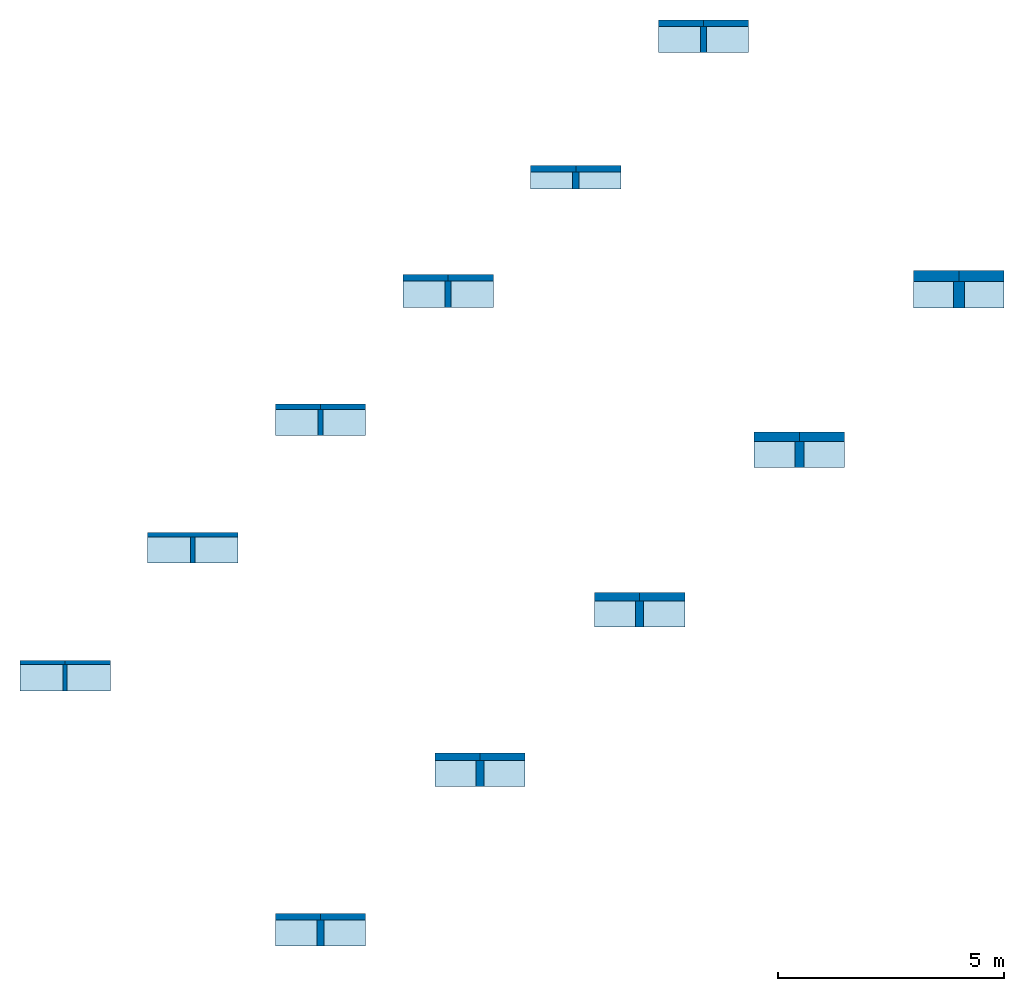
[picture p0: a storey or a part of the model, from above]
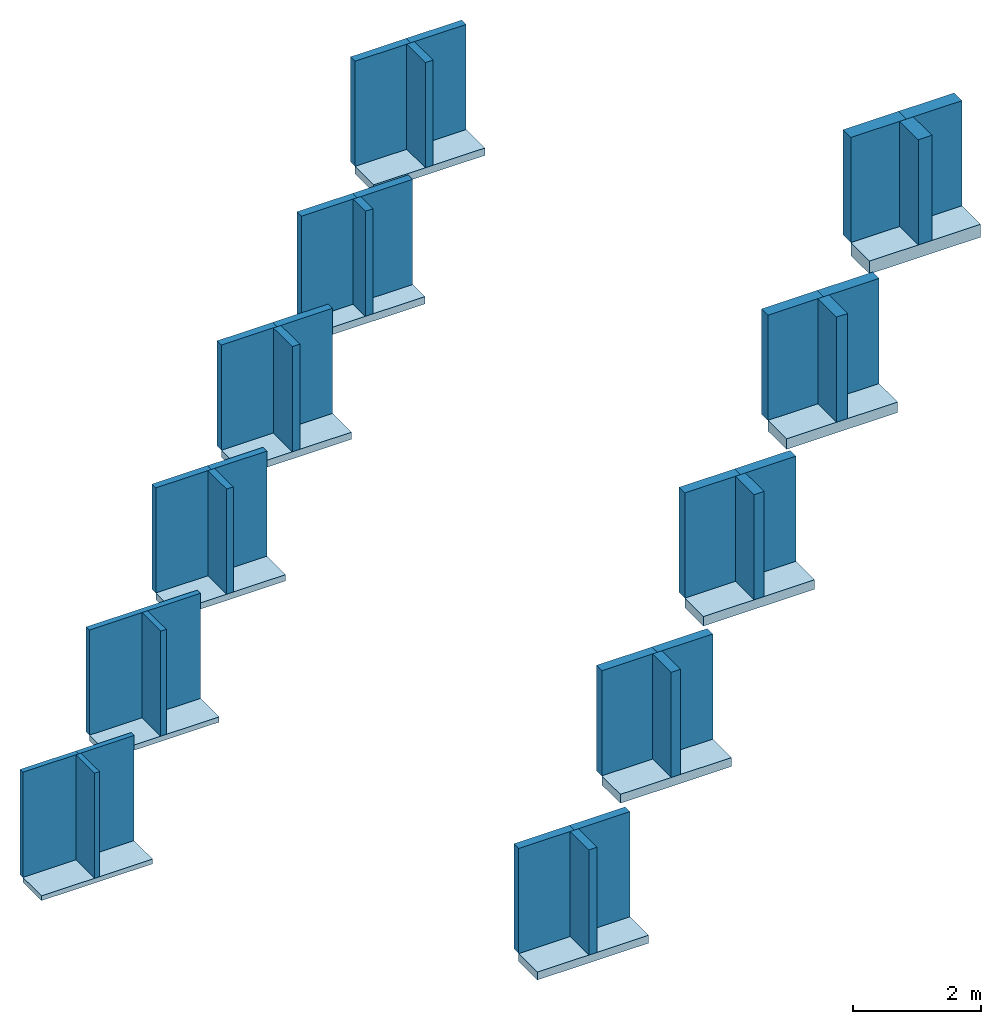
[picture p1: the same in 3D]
Properties of the parts of a building model (IFC2X3), part 1 of 2

# File
Description: ViewDefinition [CoordinationView_V2.0, QuantityTakeOffAddOnView]
Time: 2021-05-19T20:09:39
Written by: The EXPRESS Data Manager Version 5.02.0100.07 : 28 Aug 2013
Made in: 20190108_1515(x64) - Exporter 19.1.0.0 - Alternate UI 19.1.0.0
Comment: STEP Physical File produced by: The EXPRESS Data Manager Version 5.02.0100.07 : 28 Aug 2013 * Module: EDMstepFileFactory/EDMstandAlone * Creation date: Wed May 19 20:09:39 2021 * Host: lt-026 * Database: C:\Users\WF2BF~1.POE\AppData\Local\Temp\{AAD45BE6-D77A-4F7A-87E2-F376C7E0D897}\ifc * Database version: 5507 * Database creation date: Wed May 19 20:09:38 2021 * Schema: IFC2X3 * Model: DataRepository.ifc * Model creation date: Wed May 19 20:09:38 2021 * Header model: DataRepository.ifc_HeaderModel * Header model creation date: Wed May 19 20:09:38 2021 * EDMuser: sdai-user * EDMgroup: sdai-group * License ID and type: 5605 : Permanent license. Expiry date: * EDMstepFileFactory options: 020000

# IfcSite, Default
RefLatitude: 42, 24, 53, 508911; RefLongitude: -71, -15, -29, -58837; RefElevation: 0 mm
Other - Category: Project Information

# IfcBuilding
Pset_BuildingCommon - NumberOfStoreys: 2
Pset_ProductRequirements - Category: Project Information; sets with these values: 2

# IfcBuildingStorey: Level:NL_00_niveau (2)
Pset_ProductRequirements - Category: Levels
Dimensions - Computation Height: 0 mm
Identity Data - Structural: no; Building Story: yes
Other - Category: Levels; Family: Level: NL_00_niveau; Family and Type: Level: NL_00_niveau; Type: Level: NL_00_niveau; Type Id: Level: NL_00_niveau
Constraints(Type) - Elevation Base: Project Base Point
Graphics(Type) - Color: 16711680; Line Pattern: NL_00_niveau; Line Weight: 1; Symbol: NLRS_00_LAB_niveau bovenkant_gen_cadix: 1.8mm; Symbol at End 1 Default: no; Symbol at End 2 Default: yes
Identity Data(Type) - Type Name: NL_00_niveau
Other(Type) - Category: Levels; Family Name: Level
Name | LongName = Pset_AirSideSystemInformation, Name = Pset_ProductRequirements, Name = Identity Data, Name | Elevation (mm) = Constraints, Elevation (mm)
Begane grond | Begane grond | 0
Lengte | Lengte | 2000

# IfcRoof: Basic Roof:NLRS_27_RO_Naturoll 032_100x580x2700mm, Basic Roof:NLRS_27_RO_Naturoll 032_100x580x2700mm:25398
In: Lengte
Classification: 27 Daken (Uniformat)
Pset_ElementShading - Roughness: 304.8 mm
Pset_ManufacturerTypeInformation - Manufacturer: Knauf Insulation B.V.
Pset_ProductRequirements - Category: Roofs
Pset_QuantityTakeOff - Reference: NLRS_27_RO_Naturoll 032_100x580x2700mm
Pset_RoofCommon - IsExternal: yes; Reference: NLRS_27_RO_Naturoll 032_100x580x2700mm; ProjectedArea: 1.16 m2; TotalArea: 1.16 m2
Constraints - Related to Mass: no; Room Bounding: yes; Base Level: Level: Lengte; Base Offset From Level: 0 mm; Cutoff Offset: 0 mm
Construction - Fascia Depth: 0 mm; Rafter Cut: Plumb Cut; Maximum Ridge Height: 2100 mm
Dimensions - Area: 1.16 m2; Thickness: 100 mm; Volume: 0.116 m3
Other - Category: Roofs; Family: Basic Roof: NLRS_27_RO_Naturoll 032_100x580x2700mm; Family and Type: Basic Roof: NLRS_27_RO_Naturoll 032_100x580x2700mm; Type: Basic Roof: NLRS_27_RO_Naturoll 032_100x580x2700mm; Type Id: Basic Roof: NLRS_27_RO_Naturoll 032_100x580x2700mm
Phasing - Phase Created: New Construction
Analytical Properties(Type) - Roughness: 1; Thermal mass: 0; Absorptance: 0.1; Heat Transfer Coefficient (U): 0.32; Thermal Resistance (R): 3.125
Construction(Type) - Default Thickness: 100 mm
Data(Type) - rollen / pak: 2; pak (m2): 3.13; pakken / pallet: 32; pallet (m2): 100.22
Energy Analysis(Type) - kortstondige waterabsorptie: WS; langdurige waterabsorptie: WL(P); luchtstroomweerstand: Afr5; warmtegeleidingscoëfficiënt: 0.032; warmteweerstand: 3.1; waterdamptransmissie / waterdampdiffusie weerstandsfactor: MU1
General(Type) - NLRS_C_content_creator: Cadix; NLRS_C_content_versie: V1.0
Graphics(Type) - Coarse Scale Fill Color: 0
Identity Data(Type) - Type Image: Raster image: Naturoll 032 .jpg (2); Assembly Code: 27; Assembly Description: Daken; Description: Naturoll 032 - 100mm; DoP nummer (Declaration of performance): G4220OPCPR; email: customerservice.nl@knaufinsulation.com; Manufacturer: Knauf Insulation B.V.; Model: Naturoll 032 is een onbeklede glaswoldeken met ECOSE® Technology; NLRS_C_Code_Brandklasse: A1; phone: +31(0)162-421245; product URL: https://www.knaufinsulation.nl/producten-van-knauf-insulation/naturoll-032; Type Name: NLRS_27_RO_Naturoll 032_100x580x2700mm; URL: www.knaufinsulation.nl
Model Properties(Type) - diktebereik: 30 - 270; diktetolerantie: T4
Other(Type) - Category: Roofs; Family Name: Basic Roof

# IfcRoof: Basic Roof:NLRS_27_RO_Naturoll 032_120x580x2700mm, Basic Roof:NLRS_27_RO_Naturoll 032_120x580x2700mm:25438
In: Lengte
Classification: 27 Daken (Uniformat)
Pset_ElementShading - Roughness: 304.8 mm
Pset_ManufacturerTypeInformation - Manufacturer: Knauf Insulation B.V.
Pset_ProductRequirements - Category: Roofs
Pset_QuantityTakeOff - Reference: NLRS_27_RO_Naturoll 032_120x580x2700mm
Pset_RoofCommon - IsExternal: yes; Reference: NLRS_27_RO_Naturoll 032_120x580x2700mm; ProjectedArea: 1.16 m2; TotalArea: 1.16 m2
Constraints - Related to Mass: no; Room Bounding: yes; Base Level: Level: Lengte; Base Offset From Level: 0 mm; Cutoff Offset: 0 mm
Construction - Fascia Depth: 0 mm; Rafter Cut: Plumb Cut; Maximum Ridge Height: 2120 mm
Dimensions - Area: 1.16 m2; Thickness: 120 mm; Volume: 0.1392 m3
Other - Category: Roofs; Family: Basic Roof: NLRS_27_RO_Naturoll 032_120x580x2700mm; Family and Type: Basic Roof: NLRS_27_RO_Naturoll 032_120x580x2700mm; Type: Basic Roof: NLRS_27_RO_Naturoll 032_120x580x2700mm; Type Id: Basic Roof: NLRS_27_RO_Naturoll 032_120x580x2700mm
Phasing - Phase Created: New Construction
Analytical Properties(Type) - Roughness: 1; Thermal mass: 0; Absorptance: 0.1; Heat Transfer Coefficient (U): 0.266667; Thermal Resistance (R): 3.75
Construction(Type) - Default Thickness: 120 mm
Data(Type) - rollen / pak: 2; pak (m2): 3.13; pakken / pallet: 24; pallet (m2): 75.17
Energy Analysis(Type) - kortstondige waterabsorptie: WS; langdurige waterabsorptie: WL(P); luchtstroomweerstand: Afr5; warmtegeleidingscoëfficiënt: 0.032; warmteweerstand: 3.75; waterdamptransmissie / waterdampdiffusie weerstandsfactor: MU1
General(Type) - NLRS_C_content_creator: Cadix; NLRS_C_content_versie: V1.0
Graphics(Type) - Coarse Scale Fill Color: 0
Identity Data(Type) - Type Image: Raster image: Naturoll 032 .jpg (2); Assembly Code: 27; Assembly Description: Daken; Description: Naturoll 032 - 120mm; DoP nummer (Declaration of performance): G4220OPCPR; email: customerservice.nl@knaufinsulation.com; Manufacturer: Knauf Insulation B.V.; Model: Naturoll 032 is een onbeklede glaswoldeken met ECOSE® Technology; NLRS_C_Code_Brandklasse: A1; phone: +31(0)162-421245; product URL: https://www.knaufinsulation.nl/producten-van-knauf-insulation/naturoll-032; Type Name: NLRS_27_RO_Naturoll 032_120x580x2700mm; URL: www.knaufinsulation.nl
Model Properties(Type) - diktebereik: 30 - 270; diktetolerantie: T4
Other(Type) - Category: Roofs; Family Name: Basic Roof

# IfcRoof: Basic Roof:NLRS_27_RO_Naturoll 032_135x590x2700mm, Basic Roof:NLRS_27_RO_Naturoll 032_135x590x2700mm:25464
In: Lengte
Classification: 27 Daken (Uniformat)
Pset_ElementShading - Roughness: 304.8 mm
Pset_ManufacturerTypeInformation - Manufacturer: Knauf Insulation B.V.
Pset_ProductRequirements - Category: Roofs
Pset_QuantityTakeOff - Reference: NLRS_27_RO_Naturoll 032_135x590x2700mm
Pset_RoofCommon - IsExternal: yes; Reference: NLRS_27_RO_Naturoll 032_135x590x2700mm; ProjectedArea: 1.18 m2; TotalArea: 1.18 m2
Constraints - Related to Mass: no; Room Bounding: yes; Base Level: Level: Lengte; Base Offset From Level: 0 mm; Cutoff Offset: 0 mm
Construction - Fascia Depth: 0 mm; Rafter Cut: Plumb Cut; Maximum Ridge Height: 2135 mm
Dimensions - Area: 1.18 m2; Thickness: 135 mm; Volume: 0.1593 m3
Other - Category: Roofs; Family: Basic Roof: NLRS_27_RO_Naturoll 032_135x590x2700mm; Family and Type: Basic Roof: NLRS_27_RO_Naturoll 032_135x590x2700mm; Type: Basic Roof: NLRS_27_RO_Naturoll 032_135x590x2700mm; Type Id: Basic Roof: NLRS_27_RO_Naturoll 032_135x590x2700mm
Phasing - Phase Created: New Construction
Analytical Properties(Type) - Roughness: 1; Thermal mass: 0; Absorptance: 0.1; Heat Transfer Coefficient (U): 0.237037; Thermal Resistance (R): 4.21875
Construction(Type) - Default Thickness: 135 mm
Data(Type) - rollen / pak: 2; pak (m2): 3.19; pakken / pallet: 24; pallet (m2): 76.46
Energy Analysis(Type) - kortstondige waterabsorptie: WS; langdurige waterabsorptie: WL(P); luchtstroomweerstand: Afr5; warmtegeleidingscoëfficiënt: 0.032; warmteweerstand: 4.2; waterdamptransmissie / waterdampdiffusie weerstandsfactor: MU1
General(Type) - NLRS_C_content_creator: Cadix; NLRS_C_content_versie: V1.0
Graphics(Type) - Coarse Scale Fill Color: 0
Identity Data(Type) - Type Image: Raster image: Naturoll 032 .jpg (2); Assembly Code: 27; Assembly Description: Daken; Description: Naturoll 032 - 135mm; DoP nummer (Declaration of performance): G4220OPCPR; email: customerservice.nl@knaufinsulation.com; Manufacturer: Knauf Insulation B.V.; Model: Naturoll 032 is een onbeklede glaswoldeken met ECOSE® Technology; NLRS_C_Code_Brandklasse: A1; phone: +31(0)162-421245; product URL: https://www.knaufinsulation.nl/producten-van-knauf-insulation/naturoll-032; Type Name: NLRS_27_RO_Naturoll 032_135x590x2700mm; URL: www.knaufinsulation.nl
Model Properties(Type) - diktebereik: 30 - 270; diktetolerantie: T4
Other(Type) - Category: Roofs; Family Name: Basic Roof

# IfcRoof: Basic Roof:NLRS_27_RO_Naturoll 032_140x380x2700mm, Basic Roof:NLRS_27_RO_Naturoll 032_140x380x2700mm:25490
In: Lengte
Classification: 27 Daken (Uniformat)
Pset_ElementShading - Roughness: 304.8 mm
Pset_ManufacturerTypeInformation - Manufacturer: Knauf Insulation B.V.
Pset_ProductRequirements - Category: Roofs
Pset_QuantityTakeOff - Reference: NLRS_27_RO_Naturoll 032_140x380x2700mm
Pset_RoofCommon - IsExternal: yes; Reference: NLRS_27_RO_Naturoll 032_140x380x2700mm; ProjectedArea: 0.76 m2; TotalArea: 0.76 m2
Constraints - Related to Mass: no; Room Bounding: yes; Base Level: Level: Lengte; Base Offset From Level: 0 mm; Cutoff Offset: 0 mm
Construction - Fascia Depth: 0 mm; Rafter Cut: Plumb Cut; Maximum Ridge Height: 2140 mm
Dimensions - Area: 0.76 m2; Thickness: 140 mm; Volume: 0.1064 m3
Other - Category: Roofs; Family: Basic Roof: NLRS_27_RO_Naturoll 032_140x380x2700mm; Family and Type: Basic Roof: NLRS_27_RO_Naturoll 032_140x380x2700mm; Type: Basic Roof: NLRS_27_RO_Naturoll 032_140x380x2700mm; Type Id: Basic Roof: NLRS_27_RO_Naturoll 032_140x380x2700mm
Phasing - Phase Created: New Construction
Analytical Properties(Type) - Roughness: 1; Thermal mass: 0; Absorptance: 0.1; Heat Transfer Coefficient (U): 0.228571; Thermal Resistance (R): 4.375
Construction(Type) - Default Thickness: 140 mm
Data(Type) - rollen / pak: 3; pak (m2): 3.08; pakken / pallet: 24; pallet (m2): 73.87
Energy Analysis(Type) - kortstondige waterabsorptie: WS; langdurige waterabsorptie: WL(P); luchtstroomweerstand: Afr5; warmtegeleidingscoëfficiënt: 0.032; warmteweerstand: 4.35; waterdamptransmissie / waterdampdiffusie weerstandsfactor: MU1
General(Type) - NLRS_C_content_creator: Cadix; NLRS_C_content_versie: V1.0
Graphics(Type) - Coarse Scale Fill Color: 0
Identity Data(Type) - Type Image: Raster image: Naturoll 032 .jpg (2); Assembly Code: 27; Assembly Description: Daken; Description: Naturoll 032 - 140mm; DoP nummer (Declaration of performance): G4220OPCPR; email: customerservice.nl@knaufinsulation.com; Manufacturer: Knauf Insulation B.V.; Model: Naturoll 032 is een onbeklede glaswoldeken met ECOSE® Technology; NLRS_C_Code_Brandklasse: A1; phone: +31(0)162-421245; product URL: https://www.knaufinsulation.nl/producten-van-knauf-insulation/naturoll-032; Type Name: NLRS_27_RO_Naturoll 032_140x380x2700mm; URL: www.knaufinsulation.nl
Model Properties(Type) - diktebereik: 30 - 270; diktetolerantie: T4
Other(Type) - Category: Roofs; Family Name: Basic Roof

# IfcRoof: Basic Roof:NLRS_27_RO_Naturoll 032_140x580x2700mm, Basic Roof:NLRS_27_RO_Naturoll 032_140x580x2700mm:25516
In: Lengte
Classification: 27 Daken (Uniformat)
Pset_ElementShading - Roughness: 304.8 mm
Pset_ManufacturerTypeInformation - Manufacturer: Knauf Insulation B.V.
Pset_ProductRequirements - Category: Roofs
Pset_QuantityTakeOff - Reference: NLRS_27_RO_Naturoll 032_140x580x2700mm
Pset_RoofCommon - IsExternal: yes; Reference: NLRS_27_RO_Naturoll 032_140x580x2700mm; ProjectedArea: 1.16 m2; TotalArea: 1.16 m2
Constraints - Related to Mass: no; Room Bounding: yes; Base Level: Level: Lengte; Base Offset From Level: 0 mm; Cutoff Offset: 0 mm
Construction - Fascia Depth: 0 mm; Rafter Cut: Plumb Cut; Maximum Ridge Height: 2140 mm
Dimensions - Area: 1.16 m2; Thickness: 140 mm; Volume: 0.1624 m3
Other - Category: Roofs; Family: Basic Roof: NLRS_27_RO_Naturoll 032_140x580x2700mm; Family and Type: Basic Roof: NLRS_27_RO_Naturoll 032_140x580x2700mm; Type: Basic Roof: NLRS_27_RO_Naturoll 032_140x580x2700mm; Type Id: Basic Roof: NLRS_27_RO_Naturoll 032_140x580x2700mm
Phasing - Phase Created: New Construction
Analytical Properties(Type) - Roughness: 1; Thermal mass: 0; Absorptance: 0.1; Heat Transfer Coefficient (U): 0.228571; Thermal Resistance (R): 4.375
Construction(Type) - Default Thickness: 140 mm
Data(Type) - rollen / pak: 2; pak (m2): 3.13; pakken / pallet: 24; pallet (m2): 75.17
Energy Analysis(Type) - kortstondige waterabsorptie: WS; langdurige waterabsorptie: WL(P); luchtstroomweerstand: Afr5; warmtegeleidingscoëfficiënt: 0.032; warmteweerstand: 4.35; waterdamptransmissie / waterdampdiffusie weerstandsfactor: MU1
General(Type) - NLRS_C_content_creator: Cadix; NLRS_C_content_versie: V1.0
Graphics(Type) - Coarse Scale Fill Color: 0
Identity Data(Type) - Type Image: Raster image: Naturoll 032 .jpg (2); Assembly Code: 27; Assembly Description: Daken; Description: Naturoll 032 - 140mm; DoP nummer (Declaration of performance): G4220OPCPR; email: customerservice.nl@knaufinsulation.com; Manufacturer: Knauf Insulation B.V.; Model: Naturoll 032 is een onbeklede glaswoldeken met ECOSE® Technology; NLRS_C_Code_Brandklasse: A1; phone: +31(0)162-421245; product URL: https://www.knaufinsulation.nl/producten-van-knauf-insulation/naturoll-032; Type Name: NLRS_27_RO_Naturoll 032_140x580x2700mm; URL: www.knaufinsulation.nl
Model Properties(Type) - diktebereik: 30 - 270; diktetolerantie: T4
Other(Type) - Category: Roofs; Family Name: Basic Roof

# IfcRoof: Basic Roof:NLRS_27_RO_Naturoll 032_150x580x2700mm, Basic Roof:NLRS_27_RO_Naturoll 032_150x580x2700mm:26574
In: Lengte
Classification: 27 Daken (Uniformat)
Pset_ElementShading - Roughness: 304.8 mm
Pset_ManufacturerTypeInformation - Manufacturer: Knauf Insulation B.V.
Pset_ProductRequirements - Category: Roofs
Pset_QuantityTakeOff - Reference: NLRS_27_RO_Naturoll 032_150x580x2700mm
Pset_RoofCommon - IsExternal: yes; Reference: NLRS_27_RO_Naturoll 032_150x580x2700mm; ProjectedArea: 1.16 m2; TotalArea: 1.16 m2
Constraints - Related to Mass: no; Room Bounding: yes; Base Level: Level: Lengte; Base Offset From Level: 0 mm; Cutoff Offset: 0 mm
Construction - Fascia Depth: 0 mm; Rafter Cut: Plumb Cut; Maximum Ridge Height: 2150 mm
Dimensions - Area: 1.16 m2; Thickness: 150 mm; Volume: 0.174 m3
Other - Category: Roofs; Family: Basic Roof: NLRS_27_RO_Naturoll 032_150x580x2700mm; Family and Type: Basic Roof: NLRS_27_RO_Naturoll 032_150x580x2700mm; Type: Basic Roof: NLRS_27_RO_Naturoll 032_150x580x2700mm; Type Id: Basic Roof: NLRS_27_RO_Naturoll 032_150x580x2700mm
Phasing - Phase Created: New Construction
Analytical Properties(Type) - Roughness: 1; Thermal mass: 0; Absorptance: 0.1; Heat Transfer Coefficient (U): 0.213333; Thermal Resistance (R): 4.6875
Construction(Type) - Default Thickness: 150 mm
Data(Type) - rollen / pak: 2; pak (m2): 3.13; pakken / pallet: 24; pallet (m2): 75.17
Energy Analysis(Type) - kortstondige waterabsorptie: WS; langdurige waterabsorptie: WL(P); luchtstroomweerstand: Afr5; warmtegeleidingscoëfficiënt: 0.032; warmteweerstand: 4.65; waterdamptransmissie / waterdampdiffusie weerstandsfactor: MU1
General(Type) - NLRS_C_content_creator: Cadix; NLRS_C_content_versie: V1.0
Graphics(Type) - Coarse Scale Fill Color: 0
Identity Data(Type) - Type Image: Raster image: Naturoll 032 .jpg (2); Assembly Code: 27; Assembly Description: Daken; Description: Naturoll 032 - 150mm; DoP nummer (Declaration of performance): G4220OPCPR; email: customerservice.nl@knaufinsulation.com; Manufacturer: Knauf Insulation B.V.; Model: Naturoll 032 is een onbeklede glaswoldeken met ECOSE® Technology; NLRS_C_Code_Brandklasse: A1; phone: +31(0)162-421245; product URL: https://www.knaufinsulation.nl/producten-van-knauf-insulation/naturoll-032; Type Name: NLRS_27_RO_Naturoll 032_150x580x2700mm; URL: www.knaufinsulation.nl
Model Properties(Type) - diktebereik: 30 - 270; diktetolerantie: T4
Other(Type) - Category: Roofs; Family Name: Basic Roof

# IfcRoof: Basic Roof:NLRS_27_RO_Naturoll 032_170x580x3500mm, Basic Roof:NLRS_27_RO_Naturoll 032_170x580x3500mm:26836
In: Lengte
Classification: 27 Daken (Uniformat)
Pset_ElementShading - Roughness: 304.8 mm
Pset_ManufacturerTypeInformation - Manufacturer: Knauf Insulation B.V.
Pset_ProductRequirements - Category: Roofs
Pset_QuantityTakeOff - Reference: NLRS_27_RO_Naturoll 032_170x580x3500mm
Pset_RoofCommon - IsExternal: yes; Reference: NLRS_27_RO_Naturoll 032_170x580x3500mm; ProjectedArea: 1.16 m2; TotalArea: 1.16 m2
Constraints - Related to Mass: no; Room Bounding: yes; Base Level: Level: Lengte; Base Offset From Level: 0 mm; Cutoff Offset: 0 mm
Construction - Fascia Depth: 0 mm; Rafter Cut: Plumb Cut; Maximum Ridge Height: 2170 mm
Dimensions - Area: 1.16 m2; Thickness: 170 mm; Volume: 0.1972 m3
Other - Category: Roofs; Family: Basic Roof: NLRS_27_RO_Naturoll 032_170x580x3500mm; Family and Type: Basic Roof: NLRS_27_RO_Naturoll 032_170x580x3500mm; Type: Basic Roof: NLRS_27_RO_Naturoll 032_170x580x3500mm; Type Id: Basic Roof: NLRS_27_RO_Naturoll 032_170x580x3500mm
Phasing - Phase Created: New Construction
Analytical Properties(Type) - Roughness: 1; Thermal mass: 0; Absorptance: 0.1; Heat Transfer Coefficient (U): 0.188235; Thermal Resistance (R): 5.3125
Construction(Type) - Default Thickness: 170 mm
Data(Type) - rollen / pak: 2; pak (m2): 2.73; pakken / pallet: 24; pallet (m2): 65.42
Energy Analysis(Type) - kortstondige waterabsorptie: WS; langdurige waterabsorptie: WL(P); luchtstroomweerstand: Afr5; warmtegeleidingscoëfficiënt: 0.032; warmteweerstand: 5.3; waterdamptransmissie / waterdampdiffusie weerstandsfactor: MU1
General(Type) - NLRS_C_content_creator: Cadix; NLRS_C_content_versie: V1.0
Graphics(Type) - Coarse Scale Fill Color: 0
Identity Data(Type) - Type Image: Raster image: Naturoll 032 .jpg (2); Assembly Code: 27; Assembly Description: Daken; Description: Naturoll 032 - 170mm; DoP nummer (Declaration of performance): G4220OPCPR; email: customerservice.nl@knaufinsulation.com; Manufacturer: Knauf Insulation B.V.; Model: Naturoll 032 is een onbeklede glaswoldeken met ECOSE® Technology; NLRS_C_Code_Brandklasse: A1; phone: +31(0)162-421245; product URL: https://www.knaufinsulation.nl/producten-van-knauf-insulation/naturoll-032; Type Name: NLRS_27_RO_Naturoll 032_170x580x3500mm; URL: www.knaufinsulation.nl
Model Properties(Type) - diktebereik: 30 - 270; diktetolerantie: T4
Other(Type) - Category: Roofs; Family Name: Basic Roof

# IfcRoof: Basic Roof:NLRS_27_RO_Naturoll 032_180x580x2200mm, Basic Roof:NLRS_27_RO_Naturoll 032_180x580x2200mm:26894
In: Lengte
Classification: 27 Daken (Uniformat)
Pset_ElementShading - Roughness: 304.8 mm
Pset_ManufacturerTypeInformation - Manufacturer: Knauf Insulation B.V.
Pset_ProductRequirements - Category: Roofs
Pset_QuantityTakeOff - Reference: NLRS_27_RO_Naturoll 032_180x580x2200mm
Pset_RoofCommon - IsExternal: yes; Reference: NLRS_27_RO_Naturoll 032_180x580x2200mm; ProjectedArea: 1.16 m2; TotalArea: 1.16 m2
Constraints - Related to Mass: no; Room Bounding: yes; Base Level: Level: Lengte; Base Offset From Level: 0 mm; Cutoff Offset: 0 mm
Construction - Fascia Depth: 0 mm; Rafter Cut: Plumb Cut; Maximum Ridge Height: 2180 mm
Dimensions - Area: 1.16 m2; Thickness: 180 mm; Volume: 0.2088 m3
Other - Category: Roofs; Family: Basic Roof: NLRS_27_RO_Naturoll 032_180x580x2200mm; Family and Type: Basic Roof: NLRS_27_RO_Naturoll 032_180x580x2200mm; Type: Basic Roof: NLRS_27_RO_Naturoll 032_180x580x2200mm; Type Id: Basic Roof: NLRS_27_RO_Naturoll 032_180x580x2200mm
Phasing - Phase Created: New Construction
Analytical Properties(Type) - Roughness: 1; Thermal mass: 0; Absorptance: 0.1; Heat Transfer Coefficient (U): 0.177778; Thermal Resistance (R): 5.625
Construction(Type) - Default Thickness: 180 mm
Data(Type) - rollen / pak: 2; pak (m2): 2.55; pakken / pallet: 24; pallet (m2): 61.25
Energy Analysis(Type) - kortstondige waterabsorptie: WS; langdurige waterabsorptie: WL(P); luchtstroomweerstand: Afr5; warmtegeleidingscoëfficiënt: 0.032; warmteweerstand: 5.6; waterdamptransmissie / waterdampdiffusie weerstandsfactor: MU1
General(Type) - NLRS_C_content_creator: Cadix; NLRS_C_content_versie: V1.0
Graphics(Type) - Coarse Scale Fill Color: 0
Identity Data(Type) - Type Image: Raster image: Naturoll 032 .jpg (2); Assembly Code: 27; Assembly Description: Daken; Description: Naturoll 032 - 180mm; DoP nummer (Declaration of performance): G4220OPCPR; email: customerservice.nl@knaufinsulation.com; Manufacturer: Knauf Insulation B.V.; Model: Naturoll 032 is een onbeklede glaswoldeken met ECOSE® Technology; NLRS_C_Code_Brandklasse: A1; phone: +31(0)162-421245; product URL: https://www.knaufinsulation.nl/producten-van-knauf-insulation/naturoll-032; Type Name: NLRS_27_RO_Naturoll 032_180x580x2200mm; URL: www.knaufinsulation.nl
Model Properties(Type) - diktebereik: 30 - 270; diktetolerantie: T4
Other(Type) - Category: Roofs; Family Name: Basic Roof

# IfcRoof: Basic Roof:NLRS_27_RO_Naturoll 032_200x580x2000mm, Basic Roof:NLRS_27_RO_Naturoll 032_200x580x2000mm:26921
In: Lengte
Classification: 27 Daken (Uniformat)
Pset_ElementShading - Roughness: 304.8 mm
Pset_ManufacturerTypeInformation - Manufacturer: Knauf Insulation B.V.
Pset_ProductRequirements - Category: Roofs
Pset_QuantityTakeOff - Reference: NLRS_27_RO_Naturoll 032_200x580x2000mm
Pset_RoofCommon - IsExternal: yes; Reference: NLRS_27_RO_Naturoll 032_200x580x2000mm; ProjectedArea: 1.16 m2; TotalArea: 1.16 m2
Constraints - Related to Mass: no; Room Bounding: yes; Base Level: Level: Lengte; Base Offset From Level: 0 mm; Cutoff Offset: 0 mm
Construction - Fascia Depth: 0 mm; Rafter Cut: Plumb Cut; Maximum Ridge Height: 2200 mm
Dimensions - Area: 1.16 m2; Thickness: 200 mm; Volume: 0.232 m3
Other - Category: Roofs; Family: Basic Roof: NLRS_27_RO_Naturoll 032_200x580x2000mm; Family and Type: Basic Roof: NLRS_27_RO_Naturoll 032_200x580x2000mm; Type: Basic Roof: NLRS_27_RO_Naturoll 032_200x580x2000mm; Type Id: Basic Roof: NLRS_27_RO_Naturoll 032_200x580x2000mm
Phasing - Phase Created: New Construction
Analytical Properties(Type) - Roughness: 1; Thermal mass: 0; Absorptance: 0.1; Heat Transfer Coefficient (U): 0.16; Thermal Resistance (R): 6.25
Construction(Type) - Default Thickness: 200 mm
Data(Type) - rollen / pak: 2; pak (m2): 2.32; pakken / pallet: 24; pallet (m2): 55.68
Energy Analysis(Type) - kortstondige waterabsorptie: WS; langdurige waterabsorptie: WL(P); luchtstroomweerstand: Afr5; warmtegeleidingscoëfficiënt: 0.032; warmteweerstand: 6.25; waterdamptransmissie / waterdampdiffusie weerstandsfactor: MU1
General(Type) - NLRS_C_content_creator: Cadix; NLRS_C_content_versie: V1.0
Graphics(Type) - Coarse Scale Fill Color: 0
Identity Data(Type) - Type Image: Raster image: Naturoll 032 .jpg (2); Assembly Code: 27; Assembly Description: Daken; Description: Naturoll 032 - 200mm; DoP nummer (Declaration of performance): G4220OPCPR; email: customerservice.nl@knaufinsulation.com; Manufacturer: Knauf Insulation B.V.; Model: Naturoll 032 is een onbeklede glaswoldeken met ECOSE® Technology; NLRS_C_Code_Brandklasse: A1; phone: +31(0)162-421245; product URL: https://www.knaufinsulation.nl/producten-van-knauf-insulation/naturoll-032; Type Name: NLRS_27_RO_Naturoll 032_200x580x2000mm; URL: www.knaufinsulation.nl
Model Properties(Type) - diktebereik: 30 - 270; diktetolerantie: T4
Other(Type) - Category: Roofs; Family Name: Basic Roof

# IfcRoof: Basic Roof:NLRS_27_RO_Naturoll 032_245x580x2000mm, Basic Roof:NLRS_27_RO_Naturoll 032_245x580x2000mm:26948
In: Lengte
Classification: 27 Daken (Uniformat)
Pset_ElementShading - Roughness: 304.8 mm
Pset_ManufacturerTypeInformation - Manufacturer: Knauf Insulation B.V.
Pset_ProductRequirements - Category: Roofs
Pset_QuantityTakeOff - Reference: NLRS_27_RO_Naturoll 032_245x580x2000mm
Pset_RoofCommon - IsExternal: yes; Reference: NLRS_27_RO_Naturoll 032_245x580x2000mm; ProjectedArea: 1.16 m2; TotalArea: 1.16 m2
Constraints - Related to Mass: no; Room Bounding: yes; Base Level: Level: Lengte; Base Offset From Level: 0 mm; Cutoff Offset: 0 mm
Construction - Fascia Depth: 0 mm; Rafter Cut: Plumb Cut; Maximum Ridge Height: 2200 mm
Dimensions - Area: 1.16 m2; Thickness: 200 mm; Volume: 0.232 m3
Other - Category: Roofs; Family: Basic Roof: NLRS_27_RO_Naturoll 032_245x580x2000mm; Family and Type: Basic Roof: NLRS_27_RO_Naturoll 032_245x580x2000mm; Type: Basic Roof: NLRS_27_RO_Naturoll 032_245x580x2000mm; Type Id: Basic Roof: NLRS_27_RO_Naturoll 032_245x580x2000mm
Phasing - Phase Created: New Construction
Analytical Properties(Type) - Roughness: 1; Thermal mass: 0; Absorptance: 0.1; Heat Transfer Coefficient (U): 0.16; Thermal Resistance (R): 6.25
Construction(Type) - Default Thickness: 200 mm
Data(Type) - rollen / pak: 2; pak (m2): 2.32; pakken / pallet: 18; pallet (m2): 41.76
Energy Analysis(Type) - kortstondige waterabsorptie: WS; langdurige waterabsorptie: WL(P); luchtstroomweerstand: Afr5; warmtegeleidingscoëfficiënt: 0.032; warmteweerstand: 7.65; waterdamptransmissie / waterdampdiffusie weerstandsfactor: MU1
General(Type) - NLRS_C_content_creator: Cadix; NLRS_C_content_versie: V1.0
Graphics(Type) - Coarse Scale Fill Color: 0
Identity Data(Type) - Type Image: Raster image: Naturoll 032 .jpg (2); Assembly Code: 27; Assembly Description: Daken; Description: Naturoll 032 - 245mm; DoP nummer (Declaration of performance): G4220OPCPR; email: customerservice.nl@knaufinsulation.com; Manufacturer: Knauf Insulation B.V.; Model: Naturoll 032 is een onbeklede glaswoldeken met ECOSE® Technology; NLRS_C_Code_Brandklasse: A1; phone: +31(0)162-421245; product URL: https://www.knaufinsulation.nl/producten-van-knauf-insulation/naturoll-032; Type Name: NLRS_27_RO_Naturoll 032_245x580x2000mm; URL: www.knaufinsulation.nl
Model Properties(Type) - diktebereik: 30 - 270; diktetolerantie: T4
Other(Type) - Category: Roofs; Family Name: Basic Roof

# IfcRoof: Basic Roof:NLRS_27_RO_Naturoll 032_90x580x3500mm, Basic Roof:NLRS_27_RO_Naturoll 032_90x580x3500mm:25335
In: Lengte
Classification: 27 Daken (Uniformat)
Pset_ElementShading - Roughness: 304.8 mm
Pset_ManufacturerTypeInformation - Manufacturer: Knauf Insulation B.V.
Pset_ProductRequirements - Category: Roofs
Pset_QuantityTakeOff - Reference: NLRS_27_RO_Naturoll 032_90x580x3500mm
Pset_RoofCommon - IsExternal: yes; Reference: NLRS_27_RO_Naturoll 032_90x580x3500mm; ProjectedArea: 1.16 m2; TotalArea: 1.16 m2
Constraints - Related to Mass: no; Room Bounding: yes; Base Level: Level: Lengte; Base Offset From Level: 0 mm; Cutoff Offset: 0 mm
Construction - Fascia Depth: 0 mm; Maximum Ridge Height: 2090 mm; Rafter Cut: Plumb Cut
Dimensions - Area: 1.16 m2; Thickness: 90 mm; Volume: 0.1044 m3
Other - Category: Roofs; Family: Basic Roof: NLRS_27_RO_Naturoll 032_90x580x3500mm; Family and Type: Basic Roof: NLRS_27_RO_Naturoll 032_90x580x3500mm; Type: Basic Roof: NLRS_27_RO_Naturoll 032_90x580x3500mm; Type Id: Basic Roof: NLRS_27_RO_Naturoll 032_90x580x3500mm
Phasing - Phase Created: New Construction
Analytical Properties(Type) - Roughness: 1; Thermal mass: 0; Absorptance: 0.1; Heat Transfer Coefficient (U): 0.355556; Thermal Resistance (R): 2.8125
Construction(Type) - Default Thickness: 90 mm
Data(Type) - rollen / pak: 2; pak (m2): 4.06; pakken / pallet: 24; pallet (m2): 97.44
Energy Analysis(Type) - kortstondige waterabsorptie: WS; langdurige waterabsorptie: WL(P); luchtstroomweerstand: Afr5; warmtegeleidingscoëfficiënt: 0.032; warmteweerstand: 2.8; waterdamptransmissie / waterdampdiffusie weerstandsfactor: MU1
General(Type) - NLRS_C_content_creator: Cadix; NLRS_C_content_versie: V1.0
Graphics(Type) - Coarse Scale Fill Color: 0
Identity Data(Type) - Type Image: Raster image: Naturoll 032 .jpg (2); Assembly Code: 27; Assembly Description: Daken; Description: Naturoll 032 - 90mm; DoP nummer (Declaration of performance): G4220OPCPR; email: customerservice.nl@knaufinsulation.com; Manufacturer: Knauf Insulation B.V.; Model: Naturoll 032 is een onbeklede glaswoldeken met ECOSE® Technology; NLRS_C_Code_Brandklasse: A1; phone: +31(0)162-421245; product URL: https://www.knaufinsulation.nl/producten-van-knauf-insulation/naturoll-032; Type Name: NLRS_27_RO_Naturoll 032_90x580x3500mm; URL: www.knaufinsulation.nl
Model Properties(Type) - diktebereik: 30 - 270; diktetolerantie: T4
Other(Type) - Category: Roofs; Family Name: Basic Roof

# IfcSlab: Basic Roof:NLRS_27_RO_Naturoll 032_100x580x2700mm, Basic Roof:NLRS_27_RO_Naturoll 032_100x580x2700mm:25398
In: Lengte
PredefinedType: ROOF; Classification: 27 Daken (Uniformat); Material: Knauf Insulation_Ecose® glaswol_naturoll 032 100 mm
Pset_ElementShading - Roughness: 304.8 mm
Pset_ManufacturerTypeInformation - Manufacturer: Knauf Insulation B.V.
Pset_ProductRequirements - Category: Roofs
Pset_QuantityTakeOff - Reference: NLRS_27_RO_Naturoll 032_100x580x2700mm
Pset_ReinforcementBarPitchOfSlab - Description: Naturoll 032 - 100mm; Reference: NLRS_27_RO_Naturoll 032_100x580x2700mm
Pset_SlabCommon - PitchAngle: 0 deg; IsExternal: yes; Reference: NLRS_27_RO_Naturoll 032_100x580x2700mm; ThermalTransmittance: 0.32 kg/K/s3
BaseQuantities - GrossArea: 0.107768 m2; NetArea: 2.836 m2; GrossVolume: 10.7768 m3; NetVolume: 0.116 m3; Perimeter: 5160 mm; Width: 100 mm

# IfcSlab: Basic Roof:NLRS_27_RO_Naturoll 032_120x580x2700mm, Basic Roof:NLRS_27_RO_Naturoll 032_120x580x2700mm:25438
In: Lengte
PredefinedType: ROOF; Classification: 27 Daken (Uniformat); Material: Knauf Insulation_Ecose® glaswol_naturoll 032 120 mm
Pset_ElementShading - Roughness: 304.8 mm
Pset_ManufacturerTypeInformation - Manufacturer: Knauf Insulation B.V.
Pset_ProductRequirements - Category: Roofs
Pset_QuantityTakeOff - Reference: NLRS_27_RO_Naturoll 032_120x580x2700mm
Pset_ReinforcementBarPitchOfSlab - Description: Naturoll 032 - 120mm; Reference: NLRS_27_RO_Naturoll 032_120x580x2700mm
Pset_SlabCommon - PitchAngle: 0 deg; IsExternal: yes; Reference: NLRS_27_RO_Naturoll 032_120x580x2700mm; ThermalTransmittance: 0.266667 kg/K/s3
BaseQuantities - GrossArea: 0.107768 m2; NetArea: 2.9392 m2; GrossVolume: 12.9321 m3; NetVolume: 0.1392 m3; Perimeter: 5160 mm; Width: 120 mm

# IfcSlab: Basic Roof:NLRS_27_RO_Naturoll 032_135x590x2700mm, Basic Roof:NLRS_27_RO_Naturoll 032_135x590x2700mm:25464
In: Lengte
PredefinedType: ROOF; Classification: 27 Daken (Uniformat); Material: Knauf Insulation_Ecose® glaswol_naturoll 032 135 mm
Pset_ElementShading - Roughness: 304.8 mm
Pset_ManufacturerTypeInformation - Manufacturer: Knauf Insulation B.V.
Pset_ProductRequirements - Category: Roofs
Pset_QuantityTakeOff - Reference: NLRS_27_RO_Naturoll 032_135x590x2700mm
Pset_ReinforcementBarPitchOfSlab - Description: Naturoll 032 - 135mm; Reference: NLRS_27_RO_Naturoll 032_135x590x2700mm
Pset_SlabCommon - PitchAngle: 0 deg; IsExternal: yes; Reference: NLRS_27_RO_Naturoll 032_135x590x2700mm; ThermalTransmittance: 0.237037 kg/K/s3
BaseQuantities - GrossArea: 0.109626 m2; NetArea: 3.0593 m2; GrossVolume: 14.7995 m3; NetVolume: 0.1593 m3; Perimeter: 5180 mm; Width: 135 mm

# IfcSlab: Basic Roof:NLRS_27_RO_Naturoll 032_140x380x2700mm, Basic Roof:NLRS_27_RO_Naturoll 032_140x380x2700mm:25490
In: Lengte
PredefinedType: ROOF; Classification: 27 Daken (Uniformat); Material: Knauf Insulation_Ecose® glaswol_naturoll 032 140 mm
Pset_ElementShading - Roughness: 304.8 mm
Pset_ManufacturerTypeInformation - Manufacturer: Knauf Insulation B.V.
Pset_ProductRequirements - Category: Roofs
Pset_QuantityTakeOff - Reference: NLRS_27_RO_Naturoll 032_140x380x2700mm
Pset_ReinforcementBarPitchOfSlab - Description: Naturoll 032 - 140mm; Reference: NLRS_27_RO_Naturoll 032_140x380x2700mm
Pset_SlabCommon - PitchAngle: 0 deg; IsExternal: yes; Reference: NLRS_27_RO_Naturoll 032_140x380x2700mm; ThermalTransmittance: 0.228571 kg/K/s3
BaseQuantities - GrossArea: 0.0706063 m2; NetArea: 2.1864 m2; GrossVolume: 9.88488 m3; NetVolume: 0.1064 m3; Perimeter: 4760 mm; Width: 140 mm

# IfcSlab: Basic Roof:NLRS_27_RO_Naturoll 032_140x580x2700mm, Basic Roof:NLRS_27_RO_Naturoll 032_140x580x2700mm:25516
In: Lengte
PredefinedType: ROOF; Classification: 27 Daken (Uniformat); Material: Knauf Insulation_Ecose® glaswol_naturoll 032 140 mm
Pset_ElementShading - Roughness: 304.8 mm
Pset_ManufacturerTypeInformation - Manufacturer: Knauf Insulation B.V.
Pset_ProductRequirements - Category: Roofs
Pset_QuantityTakeOff - Reference: NLRS_27_RO_Naturoll 032_140x580x2700mm
Pset_ReinforcementBarPitchOfSlab - Description: Naturoll 032 - 140mm; Reference: NLRS_27_RO_Naturoll 032_140x580x2700mm
Pset_SlabCommon - PitchAngle: 0 deg; IsExternal: yes; Reference: NLRS_27_RO_Naturoll 032_140x580x2700mm; ThermalTransmittance: 0.228571 kg/K/s3
BaseQuantities - GrossArea: 0.107768 m2; NetArea: 3.0424 m2; GrossVolume: 15.0875 m3; NetVolume: 0.1624 m3; Perimeter: 5160 mm; Width: 140 mm

# IfcSlab: Basic Roof:NLRS_27_RO_Naturoll 032_150x580x2700mm, Basic Roof:NLRS_27_RO_Naturoll 032_150x580x2700mm:26574
In: Lengte
PredefinedType: ROOF; Classification: 27 Daken (Uniformat); Material: Knauf Insulation_Ecose® glaswol_naturoll 032 150 mm
Pset_ElementShading - Roughness: 304.8 mm
Pset_ManufacturerTypeInformation - Manufacturer: Knauf Insulation B.V.
Pset_ProductRequirements - Category: Roofs
Pset_QuantityTakeOff - Reference: NLRS_27_RO_Naturoll 032_150x580x2700mm
Pset_ReinforcementBarPitchOfSlab - Description: Naturoll 032 - 150mm; Reference: NLRS_27_RO_Naturoll 032_150x580x2700mm
Pset_SlabCommon - PitchAngle: 0 deg; IsExternal: yes; Reference: NLRS_27_RO_Naturoll 032_150x580x2700mm; ThermalTransmittance: 0.213333 kg/K/s3
BaseQuantities - GrossArea: 0.107768 m2; NetArea: 3.094 m2; GrossVolume: 16.1651 m3; NetVolume: 0.174 m3; Perimeter: 5160 mm; Width: 150 mm

# IfcSlab: Basic Roof:NLRS_27_RO_Naturoll 032_170x580x3500mm, Basic Roof:NLRS_27_RO_Naturoll 032_170x580x3500mm:26836
In: Lengte
PredefinedType: ROOF; Classification: 27 Daken (Uniformat); Material: Knauf Insulation_Ecose® glaswol_naturoll 032 170 mm
Pset_ElementShading - Roughness: 304.8 mm
Pset_ManufacturerTypeInformation - Manufacturer: Knauf Insulation B.V.
Pset_ProductRequirements - Category: Roofs
Pset_QuantityTakeOff - Reference: NLRS_27_RO_Naturoll 032_170x580x3500mm
Pset_ReinforcementBarPitchOfSlab - Description: Naturoll 032 - 170mm; Reference: NLRS_27_RO_Naturoll 032_170x580x3500mm
Pset_SlabCommon - PitchAngle: 0 deg; IsExternal: yes; Reference: NLRS_27_RO_Naturoll 032_170x580x3500mm; ThermalTransmittance: 0.188235 kg/K/s3
BaseQuantities - GrossArea: 0.107768 m2; NetArea: 3.1972 m2; GrossVolume: 18.3205 m3; NetVolume: 0.1972 m3; Perimeter: 5160 mm; Width: 170 mm

# IfcSlab: Basic Roof:NLRS_27_RO_Naturoll 032_180x580x2200mm, Basic Roof:NLRS_27_RO_Naturoll 032_180x580x2200mm:26894
In: Lengte
PredefinedType: ROOF; Classification: 27 Daken (Uniformat); Material: Knauf Insulation_Ecose® glaswol_naturoll 032 180 mm
Pset_ElementShading - Roughness: 304.8 mm
Pset_ManufacturerTypeInformation - Manufacturer: Knauf Insulation B.V.
Pset_ProductRequirements - Category: Roofs
Pset_QuantityTakeOff - Reference: NLRS_27_RO_Naturoll 032_180x580x2200mm
Pset_ReinforcementBarPitchOfSlab - Description: Naturoll 032 - 180mm; Reference: NLRS_27_RO_Naturoll 032_180x580x2200mm
Pset_SlabCommon - PitchAngle: 0 deg; IsExternal: yes; Reference: NLRS_27_RO_Naturoll 032_180x580x2200mm; ThermalTransmittance: 0.177778 kg/K/s3
BaseQuantities - GrossArea: 0.107768 m2; NetArea: 3.2488 m2; GrossVolume: 19.3982 m3; NetVolume: 0.2088 m3; Perimeter: 5160 mm; Width: 180 mm

# IfcSlab: Basic Roof:NLRS_27_RO_Naturoll 032_200x580x2000mm, Basic Roof:NLRS_27_RO_Naturoll 032_200x580x2000mm:26921
In: Lengte
PredefinedType: ROOF; Classification: 27 Daken (Uniformat); Material: Knauf Insulation_Ecose® glaswol_naturoll 032 200 mm
Pset_ElementShading - Roughness: 304.8 mm
Pset_ManufacturerTypeInformation - Manufacturer: Knauf Insulation B.V.
Pset_ProductRequirements - Category: Roofs
Pset_QuantityTakeOff - Reference: NLRS_27_RO_Naturoll 032_200x580x2000mm
Pset_ReinforcementBarPitchOfSlab - Description: Naturoll 032 - 200mm; Reference: NLRS_27_RO_Naturoll 032_200x580x2000mm
Pset_SlabCommon - PitchAngle: 0 deg; IsExternal: yes; Reference: NLRS_27_RO_Naturoll 032_200x580x2000mm; ThermalTransmittance: 0.16 kg/K/s3
BaseQuantities - GrossArea: 0.107768 m2; NetArea: 3.352 m2; GrossVolume: 21.5535 m3; NetVolume: 0.232 m3; Perimeter: 5160 mm; Width: 200 mm

# IfcSlab: Basic Roof:NLRS_27_RO_Naturoll 032_245x580x2000mm, Basic Roof:NLRS_27_RO_Naturoll 032_245x580x2000mm:26948
In: Lengte
PredefinedType: ROOF; Classification: 27 Daken (Uniformat); Material: Knauf Insulation_Ecose® glaswol_naturoll 032 200 mm
Pset_ElementShading - Roughness: 304.8 mm
Pset_ManufacturerTypeInformation - Manufacturer: Knauf Insulation B.V.
Pset_ProductRequirements - Category: Roofs
Pset_QuantityTakeOff - Reference: NLRS_27_RO_Naturoll 032_245x580x2000mm
Pset_ReinforcementBarPitchOfSlab - Description: Naturoll 032 - 245mm; Reference: NLRS_27_RO_Naturoll 032_245x580x2000mm
Pset_SlabCommon - PitchAngle: 0 deg; IsExternal: yes; Reference: NLRS_27_RO_Naturoll 032_245x580x2000mm; ThermalTransmittance: 0.16 kg/K/s3
BaseQuantities - GrossArea: 0.107768 m2; NetArea: 3.352 m2; GrossVolume: 21.5535 m3; NetVolume: 0.232 m3; Perimeter: 5160 mm; Width: 200 mm

# IfcSlab: Basic Roof:NLRS_27_RO_Naturoll 032_90x580x3500mm, Basic Roof:NLRS_27_RO_Naturoll 032_90x580x3500mm:25335
In: Lengte
PredefinedType: ROOF; Classification: 27 Daken (Uniformat); Material: Knauf Insulation_Ecose® glaswol_naturoll 032 90 mm
Pset_ElementShading - Roughness: 304.8 mm
Pset_ManufacturerTypeInformation - Manufacturer: Knauf Insulation B.V.
Pset_ProductRequirements - Category: Roofs
Pset_QuantityTakeOff - Reference: NLRS_27_RO_Naturoll 032_90x580x3500mm
Pset_ReinforcementBarPitchOfSlab - Description: Naturoll 032 - 90mm; Reference: NLRS_27_RO_Naturoll 032_90x580x3500mm
Pset_SlabCommon - PitchAngle: 0 deg; IsExternal: yes; Reference: NLRS_27_RO_Naturoll 032_90x580x3500mm; ThermalTransmittance: 0.355556 kg/K/s3
BaseQuantities - GrossArea: 0.107768 m2; NetArea: 2.7844 m2; GrossVolume: 9.69908 m3; NetVolume: 0.1044 m3; Perimeter: 5160 mm; Width: 90 mm

# IfcSlab: Floor:NLRS_23_FL_Naturoll 032_100x580x2700mm, Floor:NLRS_23_FL_Naturoll 032_100x580x2700mm:25387
In: Begane grond
Type - PredefinedType: FLOOR; Material: Knauf Insulation_Ecose® glaswol_naturoll 032 100 mm
Type - Analytical Properties - Roughness: 1; Thermal mass: 0; Absorptance: 0.1; Heat Transfer Coefficient (U): 0.32; Thermal Resistance (R): 3.125
Type - Construction - Function: Interior; Default Thickness: 100 mm
Type - Data - rollen / pak: 2; pak (m2): 3.13; pakken / pallet: 32; pallet (m2): 100.22
Type - Energy Analysis - kortstondige waterabsorptie: WS; langdurige waterabsorptie: WL(P); luchtstroomweerstand: Afr5; warmtegeleidingscoëfficiënt: 0.032; warmteweerstand: 3.1; waterdamptransmissie / waterdampdiffusie weerstandsfactor: MU1
Type - General - NLRS_C_content_creator: Cadix; NLRS_C_content_versie: V1.0
Type - Graphics - Coarse Scale Fill Color: 0
Type - Identity Data - Type Image: Raster image: Naturoll 032 .jpg (2); Assembly Code: 23; Assembly Description: Vloeren; Description: Naturoll 032 - 100mm; DoP nummer (Declaration of performance): G4220OPCPR; email: customerservice.nl@knaufinsulation.com; Manufacturer: Knauf Insulation B.V.; Model: Naturoll 032 is een onbeklede glaswoldeken met ECOSE® Technology; NLRS_C_Code_Brandklasse: A1; phone: +31(0)162-421245; product URL: https://www.knaufinsulation.nl/producten-van-knauf-insulation/naturoll-032; Type Name: NLRS_23_FL_Naturoll 032_100x580x2700mm; URL: www.knaufinsulation.nl
Type - Model Properties - diktebereik: 30 - 270; diktetolerantie: T4
Type - Other - Category: Floors; Family Name: Floor
Type - Pset_ElementShading - Roughness: 304.8 mm
Type - Pset_ManufacturerTypeInformation - Manufacturer: Knauf Insulation B.V.
Type - Pset_ProductRequirements - Category: Floors
Type - Pset_QuantityTakeOff - Reference: NLRS_23_FL_Naturoll 032_100x580x2700mm
Type - Pset_ReinforcementBarPitchOfSlab - Description: Naturoll 032 - 100mm; Reference: NLRS_23_FL_Naturoll 032_100x580x2700mm
Type - Pset_SlabCommon - IsExternal: no; Reference: NLRS_23_FL_Naturoll 032_100x580x2700mm; ThermalTransmittance: 0.32 kg/K/s3
Classification: 23 Vloeren (Uniformat)
Pset_SlabCommon - LoadBearing: no; PitchAngle: 0 deg
BaseQuantities - GrossArea: 1.16 m2; NetArea: 2.836 m2; GrossVolume: 116 m3; NetVolume: 0.116 m3; Perimeter: 5160 mm; Width: 100 mm
Constraints - Height Offset From Level: 0 mm; Related to Mass: no; Room Bounding: yes; Level: Level: Begane grond
Dimensions - Elevation at Top: 0 mm; Area: 1.16 m2; Elevation at Bottom: -100 mm; Perimeter: 5160 mm; Thickness: 100 mm; Volume: 0.116 m3
Other - Family: Floor: NLRS_23_FL_Naturoll 032_100x580x2700mm; Family and Type: Floor: NLRS_23_FL_Naturoll 032_100x580x2700mm; Type: Floor: NLRS_23_FL_Naturoll 032_100x580x2700mm; Type Id: Floor: NLRS_23_FL_Naturoll 032_100x580x2700mm
Phasing - Phase Created: New Construction
Structural - Enable Analytical Model: no; Structural: no

# IfcSlab: Floor:NLRS_23_FL_Naturoll 032_120x580x2700mm, Floor:NLRS_23_FL_Naturoll 032_120x580x2700mm:25427
In: Begane grond
Type - PredefinedType: FLOOR; Material: Knauf Insulation_Ecose® glaswol_naturoll 032 120 mm
Type - Analytical Properties - Roughness: 1; Thermal mass: 0; Absorptance: 0.1; Heat Transfer Coefficient (U): 0.266667; Thermal Resistance (R): 3.75
Type - Construction - Function: Interior; Default Thickness: 120 mm
Type - Data - rollen / pak: 2; pak (m2): 3.13; pakken / pallet: 24; pallet (m2): 75.17
Type - Energy Analysis - kortstondige waterabsorptie: WS; langdurige waterabsorptie: WL(P); luchtstroomweerstand: Afr5; warmtegeleidingscoëfficiënt: 0.032; warmteweerstand: 3.75; waterdamptransmissie / waterdampdiffusie weerstandsfactor: MU1
Type - General - NLRS_C_content_creator: Cadix; NLRS_C_content_versie: V1.0
Type - Graphics - Coarse Scale Fill Color: 0
Type - Identity Data - Type Image: Raster image: Naturoll 032 .jpg (2); Assembly Code: 23; Assembly Description: Vloeren; Description: Naturoll 032 - 120mm; DoP nummer (Declaration of performance): G4220OPCPR; email: customerservice.nl@knaufinsulation.com; Manufacturer: Knauf Insulation B.V.; Model: Naturoll 032 is een onbeklede glaswoldeken met ECOSE® Technology; NLRS_C_Code_Brandklasse: A1; phone: +31(0)162-421245; product URL: https://www.knaufinsulation.nl/producten-van-knauf-insulation/naturoll-032; Type Name: NLRS_23_FL_Naturoll 032_120x580x2700mm; URL: www.knaufinsulation.nl
Type - Model Properties - diktebereik: 30 - 270; diktetolerantie: T4
Type - Other - Category: Floors; Family Name: Floor
Type - Pset_ElementShading - Roughness: 304.8 mm
Type - Pset_ManufacturerTypeInformation - Manufacturer: Knauf Insulation B.V.
Type - Pset_ProductRequirements - Category: Floors
Type - Pset_QuantityTakeOff - Reference: NLRS_23_FL_Naturoll 032_120x580x2700mm
Type - Pset_ReinforcementBarPitchOfSlab - Description: Naturoll 032 - 120mm; Reference: NLRS_23_FL_Naturoll 032_120x580x2700mm
Type - Pset_SlabCommon - IsExternal: no; Reference: NLRS_23_FL_Naturoll 032_120x580x2700mm; ThermalTransmittance: 0.266667 kg/K/s3
Classification: 23 Vloeren (Uniformat)
Pset_SlabCommon - LoadBearing: no; PitchAngle: 0 deg
BaseQuantities - GrossArea: 1.16 m2; NetArea: 2.9392 m2; GrossVolume: 139.2 m3; NetVolume: 0.1392 m3; Perimeter: 5160 mm; Width: 120 mm
Constraints - Height Offset From Level: 0 mm; Level: Level: Begane grond; Related to Mass: no; Room Bounding: yes
Dimensions - Elevation at Top: 0 mm; Area: 1.16 m2; Elevation at Bottom: -120 mm; Perimeter: 5160 mm; Thickness: 120 mm; Volume: 0.1392 m3
Other - Family: Floor: NLRS_23_FL_Naturoll 032_120x580x2700mm; Family and Type: Floor: NLRS_23_FL_Naturoll 032_120x580x2700mm; Type: Floor: NLRS_23_FL_Naturoll 032_120x580x2700mm; Type Id: Floor: NLRS_23_FL_Naturoll 032_120x580x2700mm
Phasing - Phase Created: New Construction
Structural - Enable Analytical Model: no; Structural: no

# IfcSlab: Floor:NLRS_23_FL_Naturoll 032_135x590x2700mm, Floor:NLRS_23_FL_Naturoll 032_135x590x2700mm:25453
In: Begane grond
Type - PredefinedType: FLOOR; Material: Knauf Insulation_Ecose® glaswol_naturoll 032 135 mm
Type - Analytical Properties - Roughness: 1; Thermal mass: 0; Absorptance: 0.1; Heat Transfer Coefficient (U): 0.237037; Thermal Resistance (R): 4.21875
Type - Construction - Function: Interior; Default Thickness: 135 mm
Type - Data - rollen / pak: 2; pak (m2): 3.19; pakken / pallet: 24; pallet (m2): 76.46
Type - Energy Analysis - kortstondige waterabsorptie: WS; langdurige waterabsorptie: WL(P); luchtstroomweerstand: Afr5; warmtegeleidingscoëfficiënt: 0.032; warmteweerstand: 4.2; waterdamptransmissie / waterdampdiffusie weerstandsfactor: MU1
Type - General - NLRS_C_content_creator: Cadix; NLRS_C_content_versie: V1.0
Type - Graphics - Coarse Scale Fill Color: 0
Type - Identity Data - Type Image: Raster image: Naturoll 032 .jpg (2); Assembly Code: 23; Assembly Description: Vloeren; Description: Naturoll 032 - 135mm; DoP nummer (Declaration of performance): G4220OPCPR; email: customerservice.nl@knaufinsulation.com; Manufacturer: Knauf Insulation B.V.; Model: Naturoll 032 is een onbeklede glaswoldeken met ECOSE® Technology; NLRS_C_Code_Brandklasse: A1; phone: +31(0)162-421245; product URL: https://www.knaufinsulation.nl/producten-van-knauf-insulation/naturoll-032; Type Name: NLRS_23_FL_Naturoll 032_135x590x2700mm; URL: www.knaufinsulation.nl
Type - Model Properties - diktebereik: 30 - 270; diktetolerantie: T4
Type - Other - Category: Floors; Family Name: Floor
Type - Pset_ElementShading - Roughness: 304.8 mm
Type - Pset_ManufacturerTypeInformation - Manufacturer: Knauf Insulation B.V.
Type - Pset_ProductRequirements - Category: Floors
Type - Pset_QuantityTakeOff - Reference: NLRS_23_FL_Naturoll 032_135x590x2700mm
Type - Pset_ReinforcementBarPitchOfSlab - Description: Naturoll 032 - 135mm; Reference: NLRS_23_FL_Naturoll 032_135x590x2700mm
Type - Pset_SlabCommon - IsExternal: no; Reference: NLRS_23_FL_Naturoll 032_135x590x2700mm; ThermalTransmittance: 0.237037 kg/K/s3
Classification: 23 Vloeren (Uniformat)
Pset_SlabCommon - LoadBearing: no; PitchAngle: 0 deg
BaseQuantities - GrossArea: 1.18 m2; NetArea: 3.0593 m2; GrossVolume: 159.3 m3; NetVolume: 0.1593 m3; Perimeter: 5180 mm; Width: 135 mm
Constraints - Height Offset From Level: 0 mm; Level: Level: Begane grond; Related to Mass: no; Room Bounding: yes
Dimensions - Elevation at Top: 0 mm; Area: 1.18 m2; Elevation at Bottom: -135 mm; Perimeter: 5180 mm; Thickness: 135 mm; Volume: 0.1593 m3
Other - Family: Floor: NLRS_23_FL_Naturoll 032_135x590x2700mm; Family and Type: Floor: NLRS_23_FL_Naturoll 032_135x590x2700mm; Type: Floor: NLRS_23_FL_Naturoll 032_135x590x2700mm; Type Id: Floor: NLRS_23_FL_Naturoll 032_135x590x2700mm
Phasing - Phase Created: New Construction
Structural - Enable Analytical Model: no; Structural: no

# IfcSlab: Floor:NLRS_23_FL_Naturoll 032_140x380x2700mm, Floor:NLRS_23_FL_Naturoll 032_140x380x2700mm:25479
In: Begane grond
Type - PredefinedType: FLOOR; Material: Knauf Insulation_Ecose® glaswol_naturoll 032 140 mm
Type - Analytical Properties - Roughness: 1; Thermal mass: 0; Absorptance: 0.1; Heat Transfer Coefficient (U): 0.228571; Thermal Resistance (R): 4.375
Type - Construction - Function: Interior; Default Thickness: 140 mm
Type - Data - pak (m2): 3.08; pakken / pallet: 24; pallet (m2): 73.87; rollen / pak: 3
Type - Energy Analysis - kortstondige waterabsorptie: WS; langdurige waterabsorptie: WL(P); luchtstroomweerstand: Afr5; warmtegeleidingscoëfficiënt: 0.032; warmteweerstand: 4.35; waterdamptransmissie / waterdampdiffusie weerstandsfactor: MU1
Type - General - NLRS_C_content_creator: Cadix; NLRS_C_content_versie: V1.0
Type - Graphics - Coarse Scale Fill Color: 0
Type - Identity Data - Type Image: Raster image: Naturoll 032 .jpg (2); Assembly Code: 23; Assembly Description: Vloeren; Description: Naturoll 032 - 140mm; DoP nummer (Declaration of performance): G4220OPCPR; email: customerservice.nl@knaufinsulation.com; Manufacturer: Knauf Insulation B.V.; Model: Naturoll 032 is een onbeklede glaswoldeken met ECOSE® Technology; NLRS_C_Code_Brandklasse: A1; phone: +31(0)162-421245; product URL: https://www.knaufinsulation.nl/producten-van-knauf-insulation/naturoll-032; Type Name: NLRS_23_FL_Naturoll 032_140x380x2700mm; URL: www.knaufinsulation.nl
Type - Model Properties - diktebereik: 30 - 270; diktetolerantie: T4
Type - Other - Category: Floors; Family Name: Floor
Type - Pset_ElementShading - Roughness: 304.8 mm
Type - Pset_ManufacturerTypeInformation - Manufacturer: Knauf Insulation B.V.
Type - Pset_ProductRequirements - Category: Floors
Type - Pset_QuantityTakeOff - Reference: NLRS_23_FL_Naturoll 032_140x380x2700mm
Type - Pset_ReinforcementBarPitchOfSlab - Description: Naturoll 032 - 140mm; Reference: NLRS_23_FL_Naturoll 032_140x380x2700mm
Type - Pset_SlabCommon - IsExternal: no; Reference: NLRS_23_FL_Naturoll 032_140x380x2700mm; ThermalTransmittance: 0.228571 kg/K/s3
Classification: 23 Vloeren (Uniformat)
Pset_SlabCommon - LoadBearing: no; PitchAngle: 0 deg
BaseQuantities - GrossArea: 0.76 m2; NetArea: 2.1864 m2; GrossVolume: 106.4 m3; NetVolume: 0.1064 m3; Perimeter: 4760 mm; Width: 140 mm
Constraints - Height Offset From Level: 0 mm; Related to Mass: no; Room Bounding: yes; Level: Level: Begane grond
Dimensions - Elevation at Top: 0 mm; Area: 0.76 m2; Elevation at Bottom: -140 mm; Perimeter: 4760 mm; Thickness: 140 mm; Volume: 0.1064 m3
Other - Family: Floor: NLRS_23_FL_Naturoll 032_140x380x2700mm; Family and Type: Floor: NLRS_23_FL_Naturoll 032_140x380x2700mm; Type: Floor: NLRS_23_FL_Naturoll 032_140x380x2700mm; Type Id: Floor: NLRS_23_FL_Naturoll 032_140x380x2700mm
Phasing - Phase Created: New Construction
Structural - Enable Analytical Model: no; Structural: no

# IfcSlab: Floor:NLRS_23_FL_Naturoll 032_140x580x2700mm, Floor:NLRS_23_FL_Naturoll 032_140x580x2700mm:25505
In: Begane grond
Type - PredefinedType: FLOOR; Material: Knauf Insulation_Ecose® glaswol_naturoll 032 140 mm
Type - Analytical Properties - Roughness: 1; Thermal mass: 0; Absorptance: 0.1; Heat Transfer Coefficient (U): 0.228571; Thermal Resistance (R): 4.375
Type - Construction - Function: Interior; Default Thickness: 140 mm
Type - Data - rollen / pak: 2; pak (m2): 3.13; pakken / pallet: 24; pallet (m2): 75.17
Type - Energy Analysis - kortstondige waterabsorptie: WS; langdurige waterabsorptie: WL(P); luchtstroomweerstand: Afr5; warmtegeleidingscoëfficiënt: 0.032; warmteweerstand: 4.35; waterdamptransmissie / waterdampdiffusie weerstandsfactor: MU1
Type - General - NLRS_C_content_creator: Cadix; NLRS_C_content_versie: V1.0
Type - Graphics - Coarse Scale Fill Color: 0
Type - Identity Data - Type Image: Raster image: Naturoll 032 .jpg (2); Assembly Code: 23; Assembly Description: Vloeren; Description: Naturoll 032 - 140mm; DoP nummer (Declaration of performance): G4220OPCPR; email: customerservice.nl@knaufinsulation.com; Manufacturer: Knauf Insulation B.V.; Model: Naturoll 032 is een onbeklede glaswoldeken met ECOSE® Technology; NLRS_C_Code_Brandklasse: A1; phone: +31(0)162-421245; product URL: https://www.knaufinsulation.nl/producten-van-knauf-insulation/naturoll-032; Type Name: NLRS_23_FL_Naturoll 032_140x580x2700mm; URL: www.knaufinsulation.nl
Type - Model Properties - diktebereik: 30 - 270; diktetolerantie: T4
Type - Other - Category: Floors; Family Name: Floor
Type - Pset_ElementShading - Roughness: 304.8 mm
Type - Pset_ManufacturerTypeInformation - Manufacturer: Knauf Insulation B.V.
Type - Pset_ProductRequirements - Category: Floors
Type - Pset_QuantityTakeOff - Reference: NLRS_23_FL_Naturoll 032_140x580x2700mm
Type - Pset_ReinforcementBarPitchOfSlab - Description: Naturoll 032 - 140mm; Reference: NLRS_23_FL_Naturoll 032_140x580x2700mm
Type - Pset_SlabCommon - IsExternal: no; Reference: NLRS_23_FL_Naturoll 032_140x580x2700mm; ThermalTransmittance: 0.228571 kg/K/s3
Classification: 23 Vloeren (Uniformat)
Pset_SlabCommon - LoadBearing: no; PitchAngle: 0 deg
BaseQuantities - GrossArea: 1.16 m2; NetArea: 3.0424 m2; GrossVolume: 162.4 m3; NetVolume: 0.1624 m3; Perimeter: 5160 mm; Width: 140 mm
Constraints - Height Offset From Level: 0 mm; Level: Level: Begane grond; Related to Mass: no; Room Bounding: yes
Dimensions - Elevation at Top: 0 mm; Area: 1.16 m2; Elevation at Bottom: -140 mm; Perimeter: 5160 mm; Thickness: 140 mm; Volume: 0.1624 m3
Other - Family: Floor: NLRS_23_FL_Naturoll 032_140x580x2700mm; Family and Type: Floor: NLRS_23_FL_Naturoll 032_140x580x2700mm; Type: Floor: NLRS_23_FL_Naturoll 032_140x580x2700mm; Type Id: Floor: NLRS_23_FL_Naturoll 032_140x580x2700mm
Phasing - Phase Created: New Construction
Structural - Enable Analytical Model: no; Structural: no

# IfcSlab: Floor:NLRS_23_FL_Naturoll 032_150x580x2700mm, Floor:NLRS_23_FL_Naturoll 032_150x580x2700mm:26563
In: Begane grond
Type - PredefinedType: FLOOR; Material: Knauf Insulation_Ecose® glaswol_naturoll 032 150 mm
Type - Analytical Properties - Roughness: 1; Thermal mass: 0; Absorptance: 0.1; Heat Transfer Coefficient (U): 0.213333; Thermal Resistance (R): 4.6875
Type - Construction - Function: Interior; Default Thickness: 150 mm
Type - Data - rollen / pak: 2; pak (m2): 3.13; pakken / pallet: 24; pallet (m2): 75.17
Type - Energy Analysis - kortstondige waterabsorptie: WS; langdurige waterabsorptie: WL(P); luchtstroomweerstand: Afr5; warmtegeleidingscoëfficiënt: 0.032; warmteweerstand: 4.65; waterdamptransmissie / waterdampdiffusie weerstandsfactor: MU1
Type - General - NLRS_C_content_creator: Cadix; NLRS_C_content_versie: V1.0
Type - Graphics - Coarse Scale Fill Color: 0
Type - Identity Data - Type Image: Raster image: Naturoll 032 .jpg (2); Assembly Code: 23; Assembly Description: Vloeren; Description: Naturoll 032 - 150mm; DoP nummer (Declaration of performance): G4220OPCPR; email: customerservice.nl@knaufinsulation.com; Manufacturer: Knauf Insulation B.V.; Model: Naturoll 032 is een onbeklede glaswoldeken met ECOSE® Technology; NLRS_C_Code_Brandklasse: A1; phone: +31(0)162-421245; product URL: https://www.knaufinsulation.nl/producten-van-knauf-insulation/naturoll-032; Type Name: NLRS_23_FL_Naturoll 032_150x580x2700mm; URL: www.knaufinsulation.nl
Type - Model Properties - diktebereik: 30 - 270; diktetolerantie: T4
Type - Other - Category: Floors; Family Name: Floor
Type - Pset_ElementShading - Roughness: 304.8 mm
Type - Pset_ManufacturerTypeInformation - Manufacturer: Knauf Insulation B.V.
Type - Pset_ProductRequirements - Category: Floors
Type - Pset_QuantityTakeOff - Reference: NLRS_23_FL_Naturoll 032_150x580x2700mm
Type - Pset_ReinforcementBarPitchOfSlab - Description: Naturoll 032 - 150mm; Reference: NLRS_23_FL_Naturoll 032_150x580x2700mm
Type - Pset_SlabCommon - IsExternal: no; Reference: NLRS_23_FL_Naturoll 032_150x580x2700mm; ThermalTransmittance: 0.213333 kg/K/s3
Classification: 23 Vloeren (Uniformat)
Pset_SlabCommon - LoadBearing: no; PitchAngle: 0 deg
BaseQuantities - GrossArea: 1.16 m2; NetArea: 3.094 m2; GrossVolume: 174 m3; NetVolume: 0.174 m3; Perimeter: 5160 mm; Width: 150 mm
Constraints - Height Offset From Level: 0 mm; Related to Mass: no; Room Bounding: yes; Level: Level: Begane grond
Dimensions - Elevation at Top: 0 mm; Area: 1.16 m2; Elevation at Bottom: -150 mm; Perimeter: 5160 mm; Thickness: 150 mm; Volume: 0.174 m3
Other - Family: Floor: NLRS_23_FL_Naturoll 032_150x580x2700mm; Family and Type: Floor: NLRS_23_FL_Naturoll 032_150x580x2700mm; Type: Floor: NLRS_23_FL_Naturoll 032_150x580x2700mm; Type Id: Floor: NLRS_23_FL_Naturoll 032_150x580x2700mm
Phasing - Phase Created: New Construction
Structural - Enable Analytical Model: no; Structural: no

# IfcSlab: Floor:NLRS_23_FL_Naturoll 032_170x580x2350mm, Floor:NLRS_23_FL_Naturoll 032_170x580x2350mm:26825
In: Begane grond
Type - PredefinedType: FLOOR; Material: Knauf Insulation_Ecose® glaswol_naturoll 032 170 mm
Type - Analytical Properties - Roughness: 1; Thermal mass: 0; Absorptance: 0.1; Heat Transfer Coefficient (U): 0.188235; Thermal Resistance (R): 5.3125
Type - Construction - Function: Interior; Default Thickness: 170 mm
Type - Data - rollen / pak: 2; pak (m2): 2.73; pakken / pallet: 24; pallet (m2): 65.42
Type - Energy Analysis - kortstondige waterabsorptie: WS; langdurige waterabsorptie: WL(P); luchtstroomweerstand: Afr5; warmtegeleidingscoëfficiënt: 0.032; warmteweerstand: 5.3; waterdamptransmissie / waterdampdiffusie weerstandsfactor: MU1
Type - General - NLRS_C_content_creator: Cadix; NLRS_C_content_versie: V1.0
Type - Graphics - Coarse Scale Fill Color: 0
Type - Identity Data - Type Image: Raster image: Naturoll 032 .jpg (2); Assembly Code: 23; Assembly Description: Vloeren; Description: Naturoll 032 - 170mm; DoP nummer (Declaration of performance): G4220OPCPR; email: customerservice.nl@knaufinsulation.com; Manufacturer: Knauf Insulation B.V.; Model: Naturoll 032 is een onbeklede glaswoldeken met ECOSE® Technology; NLRS_C_Code_Brandklasse: A1; phone: +31(0)162-421245; product URL: https://www.knaufinsulation.nl/producten-van-knauf-insulation/naturoll-032; Type Name: NLRS_23_FL_Naturoll 032_170x580x2350mm; URL: www.knaufinsulation.nl
Type - Model Properties - diktebereik: 30 - 270; diktetolerantie: T4
Type - Other - Category: Floors; Family Name: Floor
Type - Pset_ElementShading - Roughness: 304.8 mm
Type - Pset_ManufacturerTypeInformation - Manufacturer: Knauf Insulation B.V.
Type - Pset_ProductRequirements - Category: Floors
Type - Pset_QuantityTakeOff - Reference: NLRS_23_FL_Naturoll 032_170x580x2350mm
Type - Pset_ReinforcementBarPitchOfSlab - Description: Naturoll 032 - 170mm; Reference: NLRS_23_FL_Naturoll 032_170x580x2350mm
Type - Pset_SlabCommon - IsExternal: no; Reference: NLRS_23_FL_Naturoll 032_170x580x2350mm; ThermalTransmittance: 0.188235 kg/K/s3
Classification: 23 Vloeren (Uniformat)
Pset_SlabCommon - LoadBearing: no; PitchAngle: 0 deg
BaseQuantities - GrossArea: 1.16 m2; NetArea: 3.1972 m2; GrossVolume: 197.2 m3; NetVolume: 0.1972 m3; Perimeter: 5160 mm; Width: 170 mm
Constraints - Height Offset From Level: 0 mm; Related to Mass: no; Room Bounding: yes; Level: Level: Begane grond
Dimensions - Elevation at Top: 0 mm; Area: 1.16 m2; Elevation at Bottom: -170 mm; Perimeter: 5160 mm; Thickness: 170 mm; Volume: 0.1972 m3
Other - Family: Floor: NLRS_23_FL_Naturoll 032_170x580x2350mm; Family and Type: Floor: NLRS_23_FL_Naturoll 032_170x580x2350mm; Type: Floor: NLRS_23_FL_Naturoll 032_170x580x2350mm; Type Id: Floor: NLRS_23_FL_Naturoll 032_170x580x2350mm
Phasing - Phase Created: New Construction
Structural - Enable Analytical Model: no; Structural: no

# IfcSlab: Floor:NLRS_23_FL_Naturoll 032_180x580x2200mm, Floor:NLRS_23_FL_Naturoll 032_180x580x2200mm:26883
In: Begane grond
Type - PredefinedType: FLOOR; Material: Knauf Insulation_Ecose® glaswol_naturoll 032 180 mm
Type - Analytical Properties - Roughness: 1; Thermal mass: 0; Absorptance: 0.1; Heat Transfer Coefficient (U): 0.177778; Thermal Resistance (R): 5.625
Type - Construction - Function: Interior; Default Thickness: 180 mm
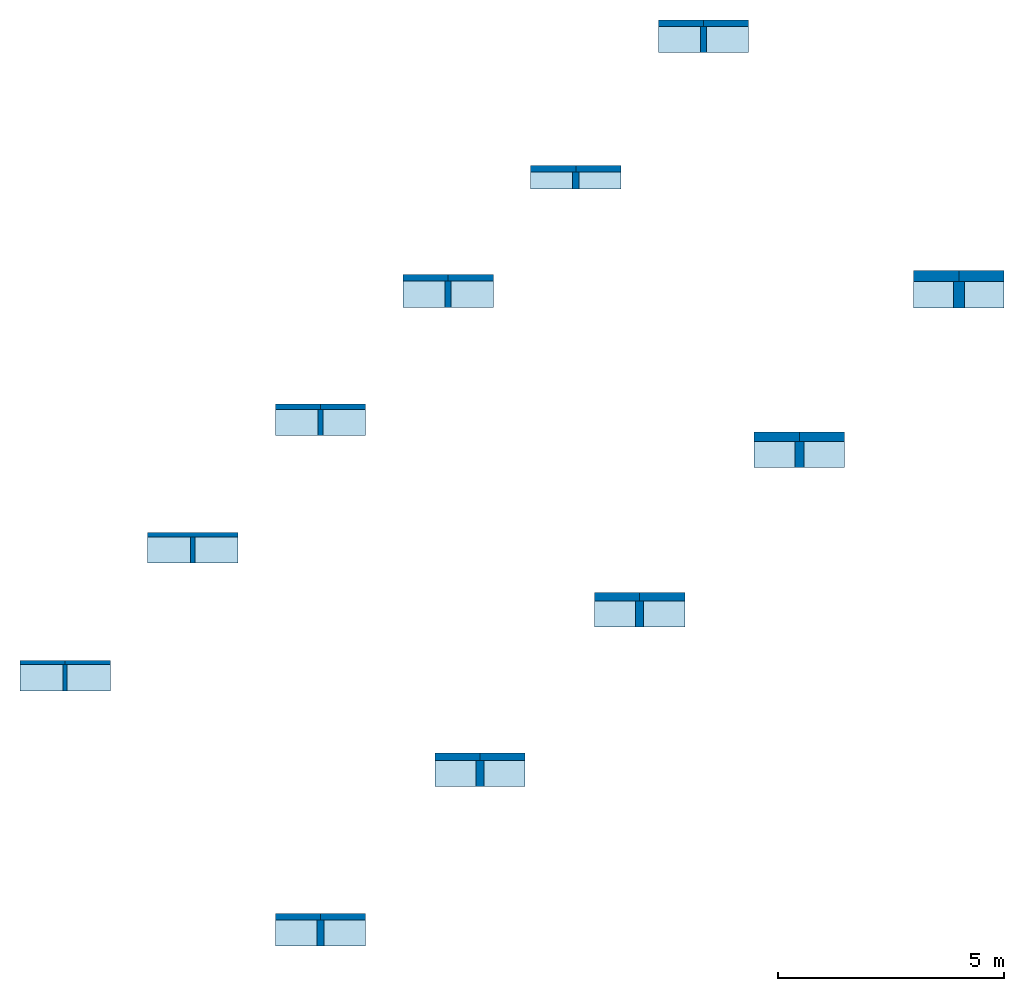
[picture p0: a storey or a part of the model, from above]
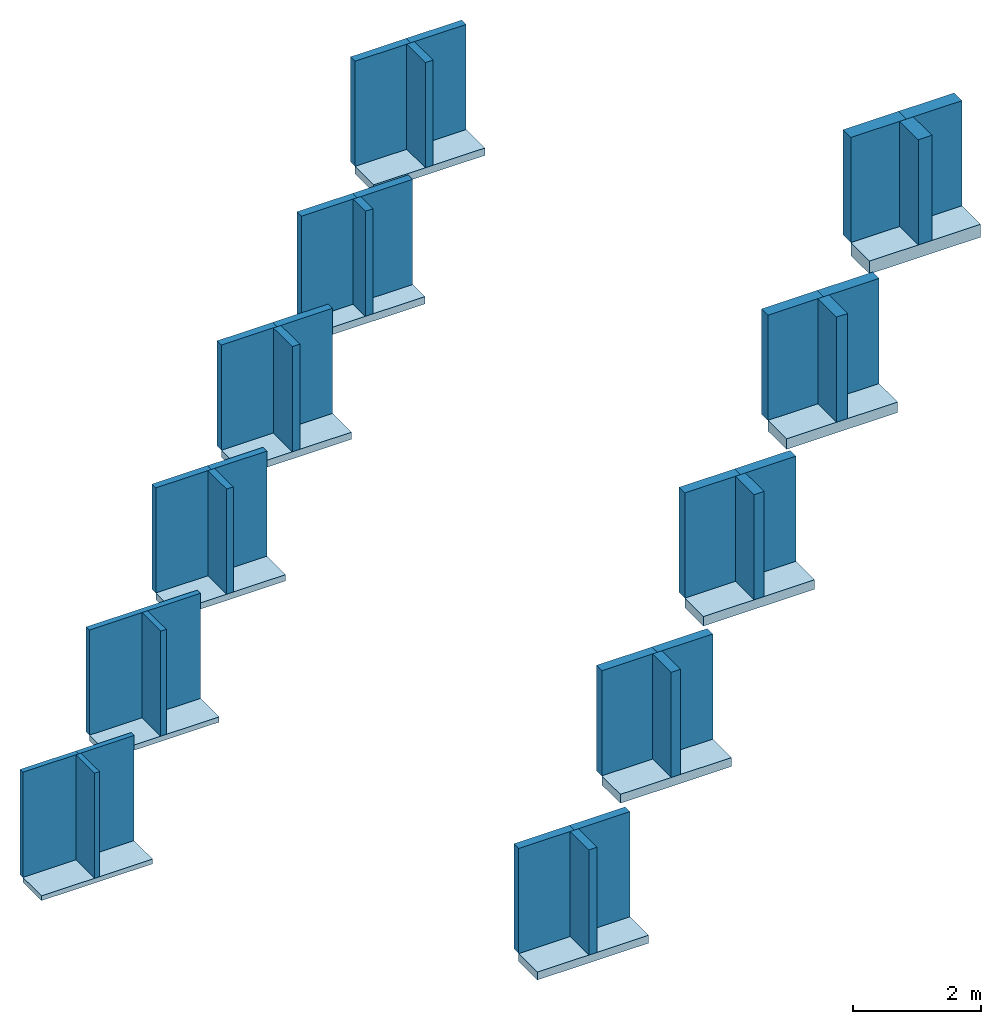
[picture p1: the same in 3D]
Properties of the parts of a building model (IFC2X3), part 2 of 2

# IfcSlab: Floor:NLRS_23_FL_Naturoll 032_180x580x2200mm, Floor:NLRS_23_FL_Naturoll 032_180x580x2200mm:26883
Type - Data - rollen / pak: 2; pak (m2): 2.55; pakken / pallet: 24; pallet (m2): 61.25
Type - Energy Analysis - kortstondige waterabsorptie: WS; langdurige waterabsorptie: WL(P); luchtstroomweerstand: Afr5; warmtegeleidingscoëfficiënt: 0.032; warmteweerstand: 5.6; waterdamptransmissie / waterdampdiffusie weerstandsfactor: MU1
Type - General - NLRS_C_content_creator: Cadix; NLRS_C_content_versie: V1.0
Type - Graphics - Coarse Scale Fill Color: 0
Type - Identity Data - Type Image: Raster image: Naturoll 032 .jpg (2); Assembly Code: 23; Assembly Description: Vloeren; Description: Naturoll 032 - 180mm; DoP nummer (Declaration of performance): G4220OPCPR; email: customerservice.nl@knaufinsulation.com; Manufacturer: Knauf Insulation B.V.; Model: Naturoll 032 is een onbeklede glaswoldeken met ECOSE® Technology; NLRS_C_Code_Brandklasse: A1; phone: +31(0)162-421245; product URL: https://www.knaufinsulation.nl/producten-van-knauf-insulation/naturoll-032; Type Name: NLRS_23_FL_Naturoll 032_180x580x2200mm; URL: www.knaufinsulation.nl
Type - Model Properties - diktebereik: 30 - 270; diktetolerantie: T4
Type - Other - Category: Floors; Family Name: Floor
Type - Pset_ElementShading - Roughness: 304.8 mm
Type - Pset_ManufacturerTypeInformation - Manufacturer: Knauf Insulation B.V.
Type - Pset_ProductRequirements - Category: Floors
Type - Pset_QuantityTakeOff - Reference: NLRS_23_FL_Naturoll 032_180x580x2200mm
Type - Pset_ReinforcementBarPitchOfSlab - Description: Naturoll 032 - 180mm; Reference: NLRS_23_FL_Naturoll 032_180x580x2200mm
Type - Pset_SlabCommon - IsExternal: no; Reference: NLRS_23_FL_Naturoll 032_180x580x2200mm; ThermalTransmittance: 0.177778 kg/K/s3
Classification: 23 Vloeren (Uniformat)
Pset_SlabCommon - LoadBearing: no; PitchAngle: 0 deg
BaseQuantities - GrossArea: 1.16 m2; NetArea: 3.2488 m2; GrossVolume: 208.8 m3; NetVolume: 0.2088 m3; Perimeter: 5160 mm; Width: 180 mm
Constraints - Height Offset From Level: 0 mm; Level: Level: Begane grond; Related to Mass: no; Room Bounding: yes
Dimensions - Elevation at Top: 0 mm; Area: 1.16 m2; Elevation at Bottom: -180 mm; Perimeter: 5160 mm; Thickness: 180 mm; Volume: 0.2088 m3
Other - Family: Floor: NLRS_23_FL_Naturoll 032_180x580x2200mm; Family and Type: Floor: NLRS_23_FL_Naturoll 032_180x580x2200mm; Type: Floor: NLRS_23_FL_Naturoll 032_180x580x2200mm; Type Id: Floor: NLRS_23_FL_Naturoll 032_180x580x2200mm
Phasing - Phase Created: New Construction
Structural - Enable Analytical Model: no; Structural: no

# IfcSlab: Floor:NLRS_23_FL_Naturoll 032_200x580x2000mm, Floor:NLRS_23_FL_Naturoll 032_200x580x2000mm:26910
In: Begane grond
Type - PredefinedType: FLOOR; Material: Knauf Insulation_Ecose® glaswol_naturoll 032 200 mm
Type - Analytical Properties - Roughness: 1; Thermal mass: 0; Absorptance: 0.1; Heat Transfer Coefficient (U): 0.16; Thermal Resistance (R): 6.25
Type - Construction - Function: Interior; Default Thickness: 200 mm
Type - Data - rollen / pak: 2; pak (m2): 2.32; pakken / pallet: 24; pallet (m2): 55.68
Type - Energy Analysis - kortstondige waterabsorptie: WS; langdurige waterabsorptie: WL(P); luchtstroomweerstand: Afr5; warmtegeleidingscoëfficiënt: 0.032; warmteweerstand: 6.25; waterdamptransmissie / waterdampdiffusie weerstandsfactor: MU1
Type - General - NLRS_C_content_creator: Cadix; NLRS_C_content_versie: V1.0
Type - Graphics - Coarse Scale Fill Color: 0
Type - Identity Data - Type Image: Raster image: Naturoll 032 .jpg (2); Assembly Code: 23; Assembly Description: Vloeren; Description: Naturoll 032 - 200mm; DoP nummer (Declaration of performance): G4220OPCPR; email: customerservice.nl@knaufinsulation.com; Manufacturer: Knauf Insulation B.V.; Model: Naturoll 032 is een onbeklede glaswoldeken met ECOSE® Technology; NLRS_C_Code_Brandklasse: A1; phone: +31(0)162-421245; product URL: https://www.knaufinsulation.nl/producten-van-knauf-insulation/naturoll-032; Type Name: NLRS_23_FL_Naturoll 032_200x580x2000mm; URL: www.knaufinsulation.nl
Type - Model Properties - diktebereik: 30 - 270; diktetolerantie: T4
Type - Other - Category: Floors; Family Name: Floor
Type - Pset_ElementShading - Roughness: 304.8 mm
Type - Pset_ManufacturerTypeInformation - Manufacturer: Knauf Insulation B.V.
Type - Pset_ProductRequirements - Category: Floors
Type - Pset_QuantityTakeOff - Reference: NLRS_23_FL_Naturoll 032_200x580x2000mm
Type - Pset_ReinforcementBarPitchOfSlab - Description: Naturoll 032 - 200mm; Reference: NLRS_23_FL_Naturoll 032_200x580x2000mm
Type - Pset_SlabCommon - IsExternal: no; Reference: NLRS_23_FL_Naturoll 032_200x580x2000mm; ThermalTransmittance: 0.16 kg/K/s3
Classification: 23 Vloeren (Uniformat)
Pset_SlabCommon - LoadBearing: no; PitchAngle: 0 deg
BaseQuantities - GrossArea: 1.16 m2; NetArea: 3.352 m2; GrossVolume: 232 m3; NetVolume: 0.232 m3; Perimeter: 5160 mm; Width: 200 mm
Constraints - Height Offset From Level: 0 mm; Level: Level: Begane grond; Related to Mass: no; Room Bounding: yes
Dimensions - Elevation at Top: 0 mm; Area: 1.16 m2; Elevation at Bottom: -200 mm; Perimeter: 5160 mm; Thickness: 200 mm; Volume: 0.232 m3
Other - Family: Floor: NLRS_23_FL_Naturoll 032_200x580x2000mm; Family and Type: Floor: NLRS_23_FL_Naturoll 032_200x580x2000mm; Type: Floor: NLRS_23_FL_Naturoll 032_200x580x2000mm; Type Id: Floor: NLRS_23_FL_Naturoll 032_200x580x2000mm
Phasing - Phase Created: New Construction
Structural - Enable Analytical Model: no; Structural: no

# IfcSlab: Floor:NLRS_23_FL_Naturoll 032_245x580x2000mm, Floor:NLRS_23_FL_Naturoll 032_245x580x2000mm:26937
In: Begane grond
Type - PredefinedType: FLOOR; Material: Knauf Insulation_Ecose® glaswol_naturoll 032 245 mm
Type - Analytical Properties - Roughness: 1; Thermal mass: 0; Absorptance: 0.1; Heat Transfer Coefficient (U): 0.130612; Thermal Resistance (R): 7.65625
Type - Construction - Function: Interior; Default Thickness: 245 mm
Type - Data - rollen / pak: 2; pak (m2): 2.32; pakken / pallet: 18; pallet (m2): 41.76
Type - Energy Analysis - kortstondige waterabsorptie: WS; langdurige waterabsorptie: WL(P); luchtstroomweerstand: Afr5; warmtegeleidingscoëfficiënt: 0.032; warmteweerstand: 7.65; waterdamptransmissie / waterdampdiffusie weerstandsfactor: MU1
Type - General - NLRS_C_content_creator: Cadix; NLRS_C_content_versie: V1.0
Type - Graphics - Coarse Scale Fill Color: 0
Type - Identity Data - Type Image: Raster image: Naturoll 032 .jpg (2); Assembly Code: 23; Assembly Description: Vloeren; Description: Naturoll 032 - 245mm; DoP nummer (Declaration of performance): G4220OPCPR; email: customerservice.nl@knaufinsulation.com; Manufacturer: Knauf Insulation B.V.; Model: Naturoll 032 is een onbeklede glaswoldeken met ECOSE® Technology; NLRS_C_Code_Brandklasse: A1; phone: +31(0)162-421245; product URL: https://www.knaufinsulation.nl/producten-van-knauf-insulation/naturoll-032; Type Name: NLRS_23_FL_Naturoll 032_245x580x2000mm; URL: www.knaufinsulation.nl
Type - Model Properties - diktebereik: 30 - 270; diktetolerantie: T4
Type - Other - Category: Floors; Family Name: Floor
Type - Pset_ElementShading - Roughness: 304.8 mm
Type - Pset_ManufacturerTypeInformation - Manufacturer: Knauf Insulation B.V.
Type - Pset_ProductRequirements - Category: Floors
Type - Pset_QuantityTakeOff - Reference: NLRS_23_FL_Naturoll 032_245x580x2000mm
Type - Pset_ReinforcementBarPitchOfSlab - Description: Naturoll 032 - 245mm; Reference: NLRS_23_FL_Naturoll 032_245x580x2000mm
Type - Pset_SlabCommon - IsExternal: no; Reference: NLRS_23_FL_Naturoll 032_245x580x2000mm; ThermalTransmittance: 0.130612 kg/K/s3
Classification: 23 Vloeren (Uniformat)
Pset_SlabCommon - LoadBearing: no; PitchAngle: 0 deg
BaseQuantities - GrossArea: 1.16 m2; NetArea: 3.5842 m2; GrossVolume: 284.2 m3; NetVolume: 0.2842 m3; Perimeter: 5160 mm; Width: 245 mm
Constraints - Height Offset From Level: 0 mm; Level: Level: Begane grond; Related to Mass: no; Room Bounding: yes
Dimensions - Elevation at Top: 0 mm; Area: 1.16 m2; Elevation at Bottom: -245 mm; Perimeter: 5160 mm; Thickness: 245 mm; Volume: 0.2842 m3
Other - Family: Floor: NLRS_23_FL_Naturoll 032_245x580x2000mm; Family and Type: Floor: NLRS_23_FL_Naturoll 032_245x580x2000mm; Type: Floor: NLRS_23_FL_Naturoll 032_245x580x2000mm; Type Id: Floor: NLRS_23_FL_Naturoll 032_245x580x2000mm
Phasing - Phase Created: New Construction
Structural - Enable Analytical Model: no; Structural: no

# IfcSlab: Floor:NLRS_23_FL_Naturoll 032_90x580x3500mm, Floor:NLRS_23_FL_Naturoll 032_90x580x3500mm:24990
In: Begane grond
Type - PredefinedType: FLOOR; Material: Knauf Insulation_Ecose® glaswol_naturoll 032 90 mm
Type - Analytical Properties - Absorptance: 0.1; Heat Transfer Coefficient (U): 0.355556; Roughness: 1; Thermal mass: 0; Thermal Resistance (R): 2.8125
Type - Construction - Default Thickness: 90 mm; Function: Interior
Type - Data - pak (m2): 4.06; pakken / pallet: 24; pallet (m2): 97.44; rollen / pak: 2
Type - Energy Analysis - kortstondige waterabsorptie: WS; langdurige waterabsorptie: WL(P); luchtstroomweerstand: Afr5; warmtegeleidingscoëfficiënt: 0.032; warmteweerstand: 2.8; waterdamptransmissie / waterdampdiffusie weerstandsfactor: MU1
Type - General - NLRS_C_content_creator: Cadix; NLRS_C_content_versie: V1.0
Type - Graphics - Coarse Scale Fill Color: 0
Type - Identity Data - Assembly Code: 23; Assembly Description: Vloeren; Description: Naturoll 032 - 90mm; DoP nummer (Declaration of performance): G4220OPCPR; email: customerservice.nl@knaufinsulation.com; Manufacturer: Knauf Insulation B.V.; Model: Naturoll 032 is een onbeklede glaswoldeken met ECOSE® Technology; NLRS_C_Code_Brandklasse: A1; phone: +31(0)162-421245; product URL: https://www.knaufinsulation.nl/producten-van-knauf-insulation/naturoll-032; Type Image: Raster image: Naturoll 032 .jpg (2); Type Name: NLRS_23_FL_Naturoll 032_90x580x3500mm; URL: www.knaufinsulation.nl
Type - Model Properties - diktebereik: 30 - 270; diktetolerantie: T4
Type - Other - Category: Floors; Family Name: Floor
Type - Pset_ElementShading - Roughness: 304.8 mm
Type - Pset_ManufacturerTypeInformation - Manufacturer: Knauf Insulation B.V.
Type - Pset_ProductRequirements - Category: Floors
Type - Pset_QuantityTakeOff - Reference: NLRS_23_FL_Naturoll 032_90x580x3500mm
Type - Pset_ReinforcementBarPitchOfSlab - Description: Naturoll 032 - 90mm; Reference: NLRS_23_FL_Naturoll 032_90x580x3500mm
Type - Pset_SlabCommon - Reference: NLRS_23_FL_Naturoll 032_90x580x3500mm; IsExternal: no; ThermalTransmittance: 0.355556 kg/K/s3
Classification: 23 Vloeren (Uniformat)
Pset_SlabCommon - LoadBearing: no; PitchAngle: 0 deg
BaseQuantities - GrossArea: 1.16 m2; NetArea: 2.7844 m2; GrossVolume: 104.4 m3; NetVolume: 0.1044 m3; Perimeter: 5160 mm; Width: 90 mm
Constraints - Height Offset From Level: 0 mm; Level: Level: Begane grond; Related to Mass: no; Room Bounding: yes
Dimensions - Area: 1.16 m2; Elevation at Bottom: -90 mm; Elevation at Top: 0 mm; Perimeter: 5160 mm; Thickness: 90 mm; Volume: 0.1044 m3
Other - Family: Floor: NLRS_23_FL_Naturoll 032_90x580x3500mm; Family and Type: Floor: NLRS_23_FL_Naturoll 032_90x580x3500mm; Type: Floor: NLRS_23_FL_Naturoll 032_90x580x3500mm; Type Id: Floor: NLRS_23_FL_Naturoll 032_90x580x3500mm
Phasing - Phase Created: New Construction
Structural - Enable Analytical Model: no; Structural: no

# IfcWallStandardCase: Basic Wall:NLRS_21_WA_Naturoll 032_100x580x2700mm (2)
In: Begane grond
Type - PredefinedType: STANDARD; Material: Knauf Insulation_Ecose® glaswol_naturoll 032 100 mm
Type - Analytical Properties - Roughness: 1; Thermal mass: 0; Absorptance: 0.1; Heat Transfer Coefficient (U): 0.32; Thermal Resistance (R): 3.125
Type - Construction - Function: Exterior; Wrapping at Inserts: Do not wrap; Width: 100 mm
Type - Data - rollen / pak: 2; pak (m2): 3.13; pakken / pallet: 32; pallet (m2): 100.22
Type - Energy Analysis - kortstondige waterabsorptie: WS; langdurige waterabsorptie: WL(P); luchtstroomweerstand: Afr5; warmtegeleidingscoëfficiënt: 0.032; warmteweerstand: 3.1; waterdamptransmissie / waterdampdiffusie weerstandsfactor: MU1
Type - General - NLRS_C_content_creator: Cadix; NLRS_C_content_versie: V1.0
Type - Graphics - Coarse Scale Fill Color: 0
Type - Identity Data - Type Image: Raster image: Naturoll 032 .jpg (2); Assembly Code: 21; Assembly Description: Buitenwanden; Description: Naturoll 032 - 100mm; DoP nummer (Declaration of performance): G4220OPCPR; email: customerservice.nl@knaufinsulation.com; Manufacturer: Knauf Insulation B.V.; Model: Naturoll 032 is een onbeklede glaswoldeken met ECOSE® Technology; NLRS_C_Code_Brandklasse: A1; phone: +31(0)162-421245; product URL: https://www.knaufinsulation.nl/producten-van-knauf-insulation/naturoll-032; Type Name: NLRS_21_WA_Naturoll 032_100x580x2700mm; URL: www.knaufinsulation.nl
Type - Model Properties - diktebereik: 30 - 270; diktetolerantie: T4
Type - Other - Category: Walls; Family Name: Basic Wall
Type - Pset_ElementShading - Roughness: 304.8 mm
Type - Pset_ManufacturerTypeInformation - Manufacturer: Knauf Insulation B.V.
Type - Pset_ProductRequirements - Category: Walls
Type - Pset_QuantityTakeOff - Reference: NLRS_21_WA_Naturoll 032_100x580x2700mm
Type - Pset_ReinforcementBarPitchOfWall - Description: Naturoll 032 - 100mm; Reference: NLRS_21_WA_Naturoll 032_100x580x2700mm
Type - Pset_WallCommon - IsExternal: no; Reference: NLRS_21_WA_Naturoll 032_100x580x2700mm; ThermalTransmittance: 0.32 kg/K/s3
Classification: 21 Buitenwanden (Uniformat)
BaseQuantities - Height: 2000 mm; Width: 100 mm
Constraints - Related to Mass: no; Room Bounding: yes; Base Constraint: Level: Begane grond; Base Extension Distance: 0 mm; Base is Attached: no; Base Offset: 0 mm; Top Constraint: Level: Lengte; Top Extension Distance: 0 mm; Top is Attached: no; Top Offset: 0 mm; Unconnected Height: 2000 mm
Other - Family: Basic Wall: NLRS_21_WA_Naturoll 032_100x580x2700mm; Family and Type: Basic Wall: NLRS_21_WA_Naturoll 032_100x580x2700mm; Type: Basic Wall: NLRS_21_WA_Naturoll 032_100x580x2700mm; Type Id: Basic Wall: NLRS_21_WA_Naturoll 032_100x580x2700mm
Phasing - Phase Created: New Construction
Structural - Enable Analytical Model: no; Structural: no; Structural Usage: Non-bearing
Pset_WallCommon - LoadBearing: no; IsExternal: yes; ExtendToStructure: no
Name (Basic Wall:NLRS_21_WA_Naturoll 032_100x580x2700mm:...) | BaseQuantities, Length (mm) = Dimensions, Length (mm) | GrossFootprintArea (m2) | NetVolume (m3) | NetSideArea (m2) | Location Line | Area (m2) | Volume (m3)
25392 | 2000 | 0.2 | 400000000 | 4000000 | Core Face: Interior | 4 | 0.4
25395 | 580 | 0.058 | 116000000 | 1160000 | Wall Centerline | 1.16 | 0.116

# IfcWallStandardCase: Basic Wall:NLRS_21_WA_Naturoll 032_120x580x2700mm (3)
In: Begane grond
Type - PredefinedType: STANDARD; Material: Knauf Insulation_Ecose® glaswol_naturoll 032 120 mm
Type - Analytical Properties - Roughness: 1; Thermal mass: 0; Absorptance: 0.1; Heat Transfer Coefficient (U): 0.266667; Thermal Resistance (R): 3.75
Type - Construction - Function: Exterior; Wrapping at Inserts: Do not wrap; Width: 120 mm
Type - Data - rollen / pak: 2; pak (m2): 3.13; pakken / pallet: 24; pallet (m2): 75.17
Type - Energy Analysis - kortstondige waterabsorptie: WS; langdurige waterabsorptie: WL(P); luchtstroomweerstand: Afr5; warmtegeleidingscoëfficiënt: 0.032; warmteweerstand: 3.75; waterdamptransmissie / waterdampdiffusie weerstandsfactor: MU1
Type - General - NLRS_C_content_creator: Cadix; NLRS_C_content_versie: V1.0
Type - Graphics - Coarse Scale Fill Color: 0
Type - Identity Data - Type Image: Raster image: Naturoll 032 .jpg (2); Assembly Code: 21; Assembly Description: Buitenwanden; Description: Naturoll 032 - 120mm; DoP nummer (Declaration of performance): G4220OPCPR; email: customerservice.nl@knaufinsulation.com; Manufacturer: Knauf Insulation B.V.; Model: Naturoll 032 is een onbeklede glaswoldeken met ECOSE® Technology; NLRS_C_Code_Brandklasse: A1; phone: +31(0)162-421245; product URL: https://www.knaufinsulation.nl/producten-van-knauf-insulation/naturoll-032; Type Name: NLRS_21_WA_Naturoll 032_120x580x2700mm; URL: www.knaufinsulation.nl
Type - Model Properties - diktebereik: 30 - 270; diktetolerantie: T4
Type - Other - Category: Walls; Family Name: Basic Wall
Type - Pset_ElementShading - Roughness: 304.8 mm
Type - Pset_ManufacturerTypeInformation - Manufacturer: Knauf Insulation B.V.
Type - Pset_ProductRequirements - Category: Walls
Type - Pset_QuantityTakeOff - Reference: NLRS_21_WA_Naturoll 032_120x580x2700mm
Type - Pset_ReinforcementBarPitchOfWall - Description: Naturoll 032 - 120mm; Reference: NLRS_21_WA_Naturoll 032_120x580x2700mm
Type - Pset_WallCommon - IsExternal: no; Reference: NLRS_21_WA_Naturoll 032_120x580x2700mm; ThermalTransmittance: 0.266667 kg/K/s3
Classification: 21 Buitenwanden (Uniformat)
BaseQuantities - Height: 2000 mm; Width: 120 mm
Constraints - Related to Mass: no; Room Bounding: yes; Base Constraint: Level: Begane grond; Base Extension Distance: 0 mm; Base is Attached: no; Base Offset: 0 mm; Top Constraint: Level: Lengte; Top Extension Distance: 0 mm; Top is Attached: no; Top Offset: 0 mm; Unconnected Height: 2000 mm
Other - Family: Basic Wall: NLRS_21_WA_Naturoll 032_120x580x2700mm; Family and Type: Basic Wall: NLRS_21_WA_Naturoll 032_120x580x2700mm; Type: Basic Wall: NLRS_21_WA_Naturoll 032_120x580x2700mm; Type Id: Basic Wall: NLRS_21_WA_Naturoll 032_120x580x2700mm
Phasing - Phase Created: New Construction
Structural - Enable Analytical Model: no; Structural: no; Structural Usage: Non-bearing
Pset_WallCommon - LoadBearing: no; IsExternal: yes; ExtendToStructure: no
Name (Basic Wall:NLRS_21_WA_Naturoll 032_120x580x2700mm:...) | BaseQuantities, Length (mm) = Dimensions, Length (mm) | GrossFootprintArea (m2) | NetVolume (m3) | NetSideArea (m2) | Location Line | Area (m2) | Volume (m3)
25432 | 1000 | 0.12 | 240000000 | 2000000 | Core Face: Interior | 2 | 0.24
25434 | 1000 | 0.12 | 240000000 | 2000000 | Core Face: Interior | 2 | 0.24
25435 | 580 | 0.0696 | 139200000 | 1160000 | Wall Centerline | 1.16 | 0.1392

# IfcWallStandardCase: Basic Wall:NLRS_21_WA_Naturoll 032_135x590x2700mm (3)
In: Begane grond
Type - PredefinedType: STANDARD; Material: Knauf Insulation_Ecose® glaswol_naturoll 032 135 mm
Type - Analytical Properties - Roughness: 1; Thermal mass: 0; Absorptance: 0.1; Heat Transfer Coefficient (U): 0.237037; Thermal Resistance (R): 4.21875
Type - Construction - Function: Exterior; Wrapping at Inserts: Do not wrap; Width: 135 mm
Type - Data - rollen / pak: 2; pak (m2): 3.19; pakken / pallet: 24; pallet (m2): 76.46
Type - Energy Analysis - kortstondige waterabsorptie: WS; langdurige waterabsorptie: WL(P); luchtstroomweerstand: Afr5; warmtegeleidingscoëfficiënt: 0.032; warmteweerstand: 4.2; waterdamptransmissie / waterdampdiffusie weerstandsfactor: MU1
Type - General - NLRS_C_content_creator: Cadix; NLRS_C_content_versie: V1.0
Type - Graphics - Coarse Scale Fill Color: 0
Type - Identity Data - Type Image: Raster image: Naturoll 032 .jpg (2); Assembly Code: 21; Assembly Description: Buitenwanden; Description: Naturoll 032 - 135mm; DoP nummer (Declaration of performance): G4220OPCPR; email: customerservice.nl@knaufinsulation.com; Manufacturer: Knauf Insulation B.V.; Model: Naturoll 032 is een onbeklede glaswoldeken met ECOSE® Technology; NLRS_C_Code_Brandklasse: A1; phone: +31(0)162-421245; product URL: https://www.knaufinsulation.nl/producten-van-knauf-insulation/naturoll-032; Type Name: NLRS_21_WA_Naturoll 032_135x590x2700mm; URL: www.knaufinsulation.nl
Type - Model Properties - diktebereik: 30 - 270; diktetolerantie: T4
Type - Other - Category: Walls; Family Name: Basic Wall
Type - Pset_ElementShading - Roughness: 304.8 mm
Type - Pset_ManufacturerTypeInformation - Manufacturer: Knauf Insulation B.V.
Type - Pset_ProductRequirements - Category: Walls
Type - Pset_QuantityTakeOff - Reference: NLRS_21_WA_Naturoll 032_135x590x2700mm
Type - Pset_ReinforcementBarPitchOfWall - Description: Naturoll 032 - 135mm; Reference: NLRS_21_WA_Naturoll 032_135x590x2700mm
Type - Pset_WallCommon - IsExternal: no; Reference: NLRS_21_WA_Naturoll 032_135x590x2700mm; ThermalTransmittance: 0.237037 kg/K/s3
Classification: 21 Buitenwanden (Uniformat)
BaseQuantities - Height: 2000 mm; Width: 135 mm
Constraints - Related to Mass: no; Room Bounding: yes; Base Constraint: Level: Begane grond; Base Extension Distance: 0 mm; Base is Attached: no; Base Offset: 0 mm; Top Constraint: Level: Lengte; Top Extension Distance: 0 mm; Top is Attached: no; Top Offset: 0 mm; Unconnected Height: 2000 mm
Other - Family: Basic Wall: NLRS_21_WA_Naturoll 032_135x590x2700mm; Family and Type: Basic Wall: NLRS_21_WA_Naturoll 032_135x590x2700mm; Type: Basic Wall: NLRS_21_WA_Naturoll 032_135x590x2700mm; Type Id: Basic Wall: NLRS_21_WA_Naturoll 032_135x590x2700mm
Phasing - Phase Created: New Construction
Structural - Enable Analytical Model: no; Structural: no; Structural Usage: Non-bearing
Pset_WallCommon - LoadBearing: no; IsExternal: yes; ExtendToStructure: no
Name (Basic Wall:NLRS_21_WA_Naturoll 032_135x590x2700mm:...) | BaseQuantities, Length (mm) = Dimensions, Length (mm) | GrossFootprintArea (m2) | NetVolume (m3) | NetSideArea (m2) | Location Line | Area (m2) | Volume (m3)
25458 | 1000 | 0.135 | 270000000 | 2000000 | Core Face: Interior | 2 | 0.27
25460 | 1000 | 0.135 | 270000000 | 2000000 | Core Face: Interior | 2 | 0.27
25461 | 590 | 0.07965 | 159300000 | 1180000 | Wall Centerline | 1.18 | 0.1593

# IfcWallStandardCase: Basic Wall:NLRS_21_WA_Naturoll 032_140x380x2700mm (3)
In: Begane grond
Type - PredefinedType: STANDARD; Material: Knauf Insulation_Ecose® glaswol_naturoll 032 140 mm
Type - Analytical Properties - Roughness: 1; Thermal mass: 0; Absorptance: 0.1; Heat Transfer Coefficient (U): 0.228571; Thermal Resistance (R): 4.375
Type - Construction - Function: Exterior; Wrapping at Inserts: Do not wrap; Width: 140 mm
Type - Data - rollen / pak: 3; pak (m2): 3.08; pakken / pallet: 24; pallet (m2): 73.87
Type - Energy Analysis - kortstondige waterabsorptie: WS; langdurige waterabsorptie: WL(P); luchtstroomweerstand: Afr5; warmtegeleidingscoëfficiënt: 0.032; warmteweerstand: 4.35; waterdamptransmissie / waterdampdiffusie weerstandsfactor: MU1
Type - General - NLRS_C_content_creator: Cadix; NLRS_C_content_versie: V1.0
Type - Graphics - Coarse Scale Fill Color: 0
Type - Identity Data - Type Image: Raster image: Naturoll 032 .jpg (2); Assembly Code: 21; Assembly Description: Buitenwanden; Description: Naturoll 032 - 140mm; DoP nummer (Declaration of performance): G4220OPCPR; email: customerservice.nl@knaufinsulation.com; Manufacturer: Knauf Insulation B.V.; Model: Naturoll 032 is een onbeklede glaswoldeken met ECOSE® Technology; NLRS_C_Code_Brandklasse: A1; phone: +31(0)162-421245; product URL: https://www.knaufinsulation.nl/producten-van-knauf-insulation/naturoll-032; Type Name: NLRS_21_WA_Naturoll 032_140x380x2700mm; URL: www.knaufinsulation.nl
Type - Model Properties - diktebereik: 30 - 270; diktetolerantie: T4
Type - Other - Category: Walls; Family Name: Basic Wall
Type - Pset_ElementShading - Roughness: 304.8 mm
Type - Pset_ManufacturerTypeInformation - Manufacturer: Knauf Insulation B.V.
Type - Pset_ProductRequirements - Category: Walls
Type - Pset_QuantityTakeOff - Reference: NLRS_21_WA_Naturoll 032_140x380x2700mm
Type - Pset_ReinforcementBarPitchOfWall - Description: Naturoll 032 - 140mm; Reference: NLRS_21_WA_Naturoll 032_140x380x2700mm
Type - Pset_WallCommon - IsExternal: no; Reference: NLRS_21_WA_Naturoll 032_140x380x2700mm; ThermalTransmittance: 0.228571 kg/K/s3
Classification: 21 Buitenwanden (Uniformat)
BaseQuantities - Height: 2000 mm; Width: 140 mm
Constraints - Related to Mass: no; Room Bounding: yes; Base Constraint: Level: Begane grond; Base Extension Distance: 0 mm; Base is Attached: no; Base Offset: 0 mm; Top Constraint: Level: Lengte; Top Extension Distance: 0 mm; Top is Attached: no; Top Offset: 0 mm; Unconnected Height: 2000 mm
Other - Family: Basic Wall: NLRS_21_WA_Naturoll 032_140x380x2700mm; Family and Type: Basic Wall: NLRS_21_WA_Naturoll 032_140x380x2700mm; Type: Basic Wall: NLRS_21_WA_Naturoll 032_140x380x2700mm; Type Id: Basic Wall: NLRS_21_WA_Naturoll 032_140x380x2700mm
Phasing - Phase Created: New Construction
Structural - Enable Analytical Model: no; Structural: no; Structural Usage: Non-bearing
Pset_WallCommon - LoadBearing: no; IsExternal: yes; ExtendToStructure: no
Name (Basic Wall:NLRS_21_WA_Naturoll 032_140x380x2700mm:...) | BaseQuantities, Length (mm) = Dimensions, Length (mm) | GrossFootprintArea (m2) | NetVolume (m3) | NetSideArea (m2) | Location Line | Area (m2) | Volume (m3)
25484 | 1000 | 0.14 | 280000000 | 2000000 | Core Face: Interior | 2 | 0.28
25486 | 1000 | 0.14 | 280000000 | 2000000 | Core Face: Interior | 2 | 0.28
25487 | 380 | 0.0532 | 106400000 | 760000 | Wall Centerline | 0.76 | 0.1064

# IfcWallStandardCase: Basic Wall:NLRS_21_WA_Naturoll 032_140x580x2700mm (3)
In: Begane grond
Type - PredefinedType: STANDARD; Material: Knauf Insulation_Ecose® glaswol_naturoll 032 140 mm
Type - Analytical Properties - Roughness: 1; Thermal mass: 0; Absorptance: 0.1; Heat Transfer Coefficient (U): 0.228571; Thermal Resistance (R): 4.375
Type - Construction - Function: Exterior; Wrapping at Inserts: Do not wrap; Width: 140 mm
Type - Data - rollen / pak: 2; pak (m2): 3.13; pakken / pallet: 24; pallet (m2): 75.17
Type - Energy Analysis - kortstondige waterabsorptie: WS; langdurige waterabsorptie: WL(P); luchtstroomweerstand: Afr5; warmtegeleidingscoëfficiënt: 0.032; warmteweerstand: 4.35; waterdamptransmissie / waterdampdiffusie weerstandsfactor: MU1
Type - General - NLRS_C_content_creator: Cadix; NLRS_C_content_versie: V1.0
Type - Graphics - Coarse Scale Fill Color: 0
Type - Identity Data - Type Image: Raster image: Naturoll 032 .jpg (2); Assembly Code: 21; Assembly Description: Buitenwanden; Description: Naturoll 032 - 140mm; DoP nummer (Declaration of performance): G4220OPCPR; email: customerservice.nl@knaufinsulation.com; Manufacturer: Knauf Insulation B.V.; Model: Naturoll 032 is een onbeklede glaswoldeken met ECOSE® Technology; NLRS_C_Code_Brandklasse: A1; phone: +31(0)162-421245; product URL: https://www.knaufinsulation.nl/producten-van-knauf-insulation/naturoll-032; Type Name: NLRS_21_WA_Naturoll 032_140x580x2700mm; URL: www.knaufinsulation.nl
Type - Model Properties - diktebereik: 30 - 270; diktetolerantie: T4
Type - Other - Category: Walls; Family Name: Basic Wall
Type - Pset_ElementShading - Roughness: 304.8 mm
Type - Pset_ManufacturerTypeInformation - Manufacturer: Knauf Insulation B.V.
Type - Pset_ProductRequirements - Category: Walls
Type - Pset_QuantityTakeOff - Reference: NLRS_21_WA_Naturoll 032_140x580x2700mm
Type - Pset_ReinforcementBarPitchOfWall - Description: Naturoll 032 - 140mm; Reference: NLRS_21_WA_Naturoll 032_140x580x2700mm
Type - Pset_WallCommon - IsExternal: no; Reference: NLRS_21_WA_Naturoll 032_140x580x2700mm; ThermalTransmittance: 0.228571 kg/K/s3
Classification: 21 Buitenwanden (Uniformat)
BaseQuantities - Height: 2000 mm; Width: 140 mm
Constraints - Related to Mass: no; Room Bounding: yes; Base Constraint: Level: Begane grond; Base Extension Distance: 0 mm; Base is Attached: no; Base Offset: 0 mm; Top Constraint: Level: Lengte; Top Extension Distance: 0 mm; Top is Attached: no; Top Offset: 0 mm; Unconnected Height: 2000 mm
Other - Family: Basic Wall: NLRS_21_WA_Naturoll 032_140x580x2700mm; Family and Type: Basic Wall: NLRS_21_WA_Naturoll 032_140x580x2700mm; Type: Basic Wall: NLRS_21_WA_Naturoll 032_140x580x2700mm; Type Id: Basic Wall: NLRS_21_WA_Naturoll 032_140x580x2700mm
Phasing - Phase Created: New Construction
Structural - Enable Analytical Model: no; Structural: no; Structural Usage: Non-bearing
Pset_WallCommon - LoadBearing: no; IsExternal: yes; ExtendToStructure: no
Name (Basic Wall:NLRS_21_WA_Naturoll 032_140x580x2700mm:...) | BaseQuantities, Length (mm) = Dimensions, Length (mm) | GrossFootprintArea (m2) | NetVolume (m3) | NetSideArea (m2) | Location Line | Area (m2) | Volume (m3)
25510 | 1000 | 0.14 | 280000000 | 2000000 | Core Face: Interior | 2 | 0.28
25512 | 1000 | 0.14 | 280000000 | 2000000 | Core Face: Interior | 2 | 0.28
25513 | 580 | 0.0812 | 162400000 | 1160000 | Wall Centerline | 1.16 | 0.1624

# IfcWallStandardCase: Basic Wall:NLRS_21_WA_Naturoll 032_150x580x2700mm (3)
In: Begane grond
Type - PredefinedType: STANDARD; Material: Knauf Insulation_Ecose® glaswol_naturoll 032 150 mm
Type - Analytical Properties - Roughness: 1; Thermal mass: 0; Absorptance: 0.1; Heat Transfer Coefficient (U): 0.213333; Thermal Resistance (R): 4.6875
Type - Construction - Function: Exterior; Wrapping at Inserts: Do not wrap; Width: 150 mm
Type - Data - rollen / pak: 2; pak (m2): 3.13; pakken / pallet: 24; pallet (m2): 75.17
Type - Energy Analysis - kortstondige waterabsorptie: WS; langdurige waterabsorptie: WL(P); luchtstroomweerstand: Afr5; warmtegeleidingscoëfficiënt: 0.032; warmteweerstand: 4.65; waterdamptransmissie / waterdampdiffusie weerstandsfactor: MU1
Type - General - NLRS_C_content_creator: Cadix; NLRS_C_content_versie: V1.0
Type - Graphics - Coarse Scale Fill Color: 0
Type - Identity Data - Type Image: Raster image: Naturoll 032 .jpg (2); Assembly Code: 21; Assembly Description: Buitenwanden; Description: Naturoll 032 - 150mm; DoP nummer (Declaration of performance): G4220OPCPR; email: customerservice.nl@knaufinsulation.com; Manufacturer: Knauf Insulation B.V.; Model: Naturoll 032 is een onbeklede glaswoldeken met ECOSE® Technology; NLRS_C_Code_Brandklasse: A1; phone: +31(0)162-421245; product URL: https://www.knaufinsulation.nl/producten-van-knauf-insulation/naturoll-032; Type Name: NLRS_21_WA_Naturoll 032_150x580x2700mm; URL: www.knaufinsulation.nl
Type - Model Properties - diktebereik: 30 - 270; diktetolerantie: T4
Type - Other - Category: Walls; Family Name: Basic Wall
Type - Pset_ElementShading - Roughness: 304.8 mm
Type - Pset_ManufacturerTypeInformation - Manufacturer: Knauf Insulation B.V.
Type - Pset_ProductRequirements - Category: Walls
Type - Pset_QuantityTakeOff - Reference: NLRS_21_WA_Naturoll 032_150x580x2700mm
Type - Pset_ReinforcementBarPitchOfWall - Description: Naturoll 032 - 150mm; Reference: NLRS_21_WA_Naturoll 032_150x580x2700mm
Type - Pset_WallCommon - IsExternal: no; Reference: NLRS_21_WA_Naturoll 032_150x580x2700mm; ThermalTransmittance: 0.213333 kg/K/s3
Classification: 21 Buitenwanden (Uniformat)
BaseQuantities - Height: 2000 mm; Width: 150 mm
Constraints - Related to Mass: no; Room Bounding: yes; Base Constraint: Level: Begane grond; Base Extension Distance: 0 mm; Base is Attached: no; Base Offset: 0 mm; Top Constraint: Level: Lengte; Top Extension Distance: 0 mm; Top is Attached: no; Top Offset: 0 mm; Unconnected Height: 2000 mm
Other - Family: Basic Wall: NLRS_21_WA_Naturoll 032_150x580x2700mm; Family and Type: Basic Wall: NLRS_21_WA_Naturoll 032_150x580x2700mm; Type: Basic Wall: NLRS_21_WA_Naturoll 032_150x580x2700mm; Type Id: Basic Wall: NLRS_21_WA_Naturoll 032_150x580x2700mm
Phasing - Phase Created: New Construction
Structural - Enable Analytical Model: no; Structural: no; Structural Usage: Non-bearing
Pset_WallCommon - LoadBearing: no; IsExternal: yes; ExtendToStructure: no
Name (Basic Wall:NLRS_21_WA_Naturoll 032_150x580x2700mm:...) | BaseQuantities, Length (mm) = Dimensions, Length (mm) | GrossFootprintArea (m2) | NetVolume (m3) | NetSideArea (m2) | Location Line | Area (m2) | Volume (m3)
26568 | 1000 | 0.15 | 300000000 | 2000000 | Core Face: Interior | 2 | 0.3
26570 | 1000 | 0.15 | 300000000 | 2000000 | Core Face: Interior | 2 | 0.3
26571 | 580 | 0.087 | 174000000 | 1160000 | Wall Centerline | 1.16 | 0.174

# IfcWallStandardCase: Basic Wall:NLRS_21_WA_Naturoll 032_170x580x2350mm (3)
In: Begane grond
Type - PredefinedType: STANDARD; Material: Knauf Insulation_Ecose® glaswol_naturoll 032 170 mm
Type - Analytical Properties - Roughness: 1; Thermal mass: 0; Absorptance: 0.1; Heat Transfer Coefficient (U): 0.188235; Thermal Resistance (R): 5.3125
Type - Construction - Function: Exterior; Wrapping at Inserts: Do not wrap; Width: 170 mm
Type - Data - rollen / pak: 2; pak (m2): 2.73; pakken / pallet: 24; pallet (m2): 65.42
Type - Energy Analysis - kortstondige waterabsorptie: WS; langdurige waterabsorptie: WL(P); luchtstroomweerstand: Afr5; warmtegeleidingscoëfficiënt: 0.032; warmteweerstand: 5.3; waterdamptransmissie / waterdampdiffusie weerstandsfactor: MU1
Type - General - NLRS_C_content_creator: Cadix; NLRS_C_content_versie: V1.0
Type - Graphics - Coarse Scale Fill Color: 0
Type - Identity Data - Type Image: Raster image: Naturoll 032 .jpg (2); Assembly Code: 21; Assembly Description: Buitenwanden; Description: Naturoll 032 - 170mm; DoP nummer (Declaration of performance): G4220OPCPR; email: customerservice.nl@knaufinsulation.com; Manufacturer: Knauf Insulation B.V.; Model: Naturoll 032 is een onbeklede glaswoldeken met ECOSE® Technology; NLRS_C_Code_Brandklasse: A1; phone: +31(0)162-421245; product URL: https://www.knaufinsulation.nl/producten-van-knauf-insulation/naturoll-032; Type Name: NLRS_21_WA_Naturoll 032_170x580x2350mm; URL: www.knaufinsulation.nl
Type - Model Properties - diktebereik: 30 - 270; diktetolerantie: T4
Type - Other - Category: Walls; Family Name: Basic Wall
Type - Pset_ElementShading - Roughness: 304.8 mm
Type - Pset_ManufacturerTypeInformation - Manufacturer: Knauf Insulation B.V.
Type - Pset_ProductRequirements - Category: Walls
Type - Pset_QuantityTakeOff - Reference: NLRS_21_WA_Naturoll 032_170x580x2350mm
Type - Pset_ReinforcementBarPitchOfWall - Description: Naturoll 032 - 170mm; Reference: NLRS_21_WA_Naturoll 032_170x580x2350mm
Type - Pset_WallCommon - IsExternal: no; Reference: NLRS_21_WA_Naturoll 032_170x580x2350mm; ThermalTransmittance: 0.188235 kg/K/s3
Classification: 21 Buitenwanden (Uniformat)
BaseQuantities - Height: 2000 mm; Width: 170 mm
Constraints - Related to Mass: no; Room Bounding: yes; Base Constraint: Level: Begane grond; Base Extension Distance: 0 mm; Base is Attached: no; Base Offset: 0 mm; Top Constraint: Level: Lengte; Top Extension Distance: 0 mm; Top is Attached: no; Top Offset: 0 mm; Unconnected Height: 2000 mm
Other - Family: Basic Wall: NLRS_21_WA_Naturoll 032_170x580x2350mm; Family and Type: Basic Wall: NLRS_21_WA_Naturoll 032_170x580x2350mm; Type: Basic Wall: NLRS_21_WA_Naturoll 032_170x580x2350mm; Type Id: Basic Wall: NLRS_21_WA_Naturoll 032_170x580x2350mm
Phasing - Phase Created: New Construction
Structural - Enable Analytical Model: no; Structural: no; Structural Usage: Non-bearing
Pset_WallCommon - LoadBearing: no; IsExternal: yes; ExtendToStructure: no
Name (Basic Wall:NLRS_21_WA_Naturoll 032_170x580x2350mm:...) | BaseQuantities, Length (mm) = Dimensions, Length (mm) | GrossFootprintArea (m2) | NetVolume (m3) | NetSideArea (m2) | Location Line | Area (m2) | Volume (m3)
26830 | 1000 | 0.17 | 340000000 | 2000000 | Core Face: Interior | 2 | 0.34
26832 | 1000 | 0.17 | 340000000 | 2000000 | Core Face: Interior | 2 | 0.34
26833 | 580 | 0.0986 | 197200000 | 1160000 | Wall Centerline | 1.16 | 0.1972

# IfcWallStandardCase: Basic Wall:NLRS_21_WA_Naturoll 032_180x580x2200mm (3)
In: Begane grond
Type - PredefinedType: STANDARD; Material: Knauf Insulation_Ecose® glaswol_naturoll 032 180 mm
Type - Analytical Properties - Roughness: 1; Thermal mass: 0; Absorptance: 0.1; Heat Transfer Coefficient (U): 0.177778; Thermal Resistance (R): 5.625
Type - Construction - Function: Exterior; Wrapping at Inserts: Do not wrap; Width: 180 mm
Type - Data - rollen / pak: 2; pak (m2): 2.55; pakken / pallet: 24; pallet (m2): 61.25
Type - Energy Analysis - kortstondige waterabsorptie: WS; langdurige waterabsorptie: WL(P); luchtstroomweerstand: Afr5; warmtegeleidingscoëfficiënt: 0.032; warmteweerstand: 5.6; waterdamptransmissie / waterdampdiffusie weerstandsfactor: MU1
Type - General - NLRS_C_content_creator: Cadix; NLRS_C_content_versie: V1.0
Type - Graphics - Coarse Scale Fill Color: 0
Type - Identity Data - Type Image: Raster image: Naturoll 032 .jpg (2); Assembly Code: 21; Assembly Description: Buitenwanden; Description: Naturoll 032 - 180mm; DoP nummer (Declaration of performance): G4220OPCPR; email: customerservice.nl@knaufinsulation.com; Manufacturer: Knauf Insulation B.V.; Model: Naturoll 032 is een onbeklede glaswoldeken met ECOSE® Technology; NLRS_C_Code_Brandklasse: A1; phone: +31(0)162-421245; product URL: https://www.knaufinsulation.nl/producten-van-knauf-insulation/naturoll-032; Type Name: NLRS_21_WA_Naturoll 032_180x580x2200mm; URL: www.knaufinsulation.nl
Type - Model Properties - diktebereik: 30 - 270; diktetolerantie: T4
Type - Other - Category: Walls; Family Name: Basic Wall
Type - Pset_ElementShading - Roughness: 304.8 mm
Type - Pset_ManufacturerTypeInformation - Manufacturer: Knauf Insulation B.V.
Type - Pset_ProductRequirements - Category: Walls
Type - Pset_QuantityTakeOff - Reference: NLRS_21_WA_Naturoll 032_180x580x2200mm
Type - Pset_ReinforcementBarPitchOfWall - Description: Naturoll 032 - 180mm; Reference: NLRS_21_WA_Naturoll 032_180x580x2200mm
Type - Pset_WallCommon - IsExternal: no; Reference: NLRS_21_WA_Naturoll 032_180x580x2200mm; ThermalTransmittance: 0.177778 kg/K/s3
Classification: 21 Buitenwanden (Uniformat)
BaseQuantities - Height: 2000 mm; Width: 180 mm
Constraints - Related to Mass: no; Room Bounding: yes; Base Constraint: Level: Begane grond; Base Extension Distance: 0 mm; Base is Attached: no; Base Offset: 0 mm; Top Constraint: Level: Lengte; Top Extension Distance: 0 mm; Top is Attached: no; Top Offset: 0 mm; Unconnected Height: 2000 mm
Other - Family: Basic Wall: NLRS_21_WA_Naturoll 032_180x580x2200mm; Family and Type: Basic Wall: NLRS_21_WA_Naturoll 032_180x580x2200mm; Type: Basic Wall: NLRS_21_WA_Naturoll 032_180x580x2200mm; Type Id: Basic Wall: NLRS_21_WA_Naturoll 032_180x580x2200mm
Phasing - Phase Created: New Construction
Structural - Enable Analytical Model: no; Structural: no; Structural Usage: Non-bearing
Pset_WallCommon - LoadBearing: no; IsExternal: yes; ExtendToStructure: no
Name (Basic Wall:NLRS_21_WA_Naturoll 032_180x580x2200mm:...) | BaseQuantities, Length (mm) = Dimensions, Length (mm) | GrossFootprintArea (m2) | NetVolume (m3) | NetSideArea (m2) | Location Line | Area (m2) | Volume (m3)
26888 | 1000 | 0.18 | 360000000 | 2000000 | Core Face: Interior | 2 | 0.36
26890 | 1000 | 0.18 | 360000000 | 2000000 | Core Face: Interior | 2 | 0.36
26891 | 580 | 0.1044 | 208800000 | 1160000 | Wall Centerline | 1.16 | 0.2088

# IfcWallStandardCase: Basic Wall:NLRS_21_WA_Naturoll 032_200x580x2000mm (3)
In: Begane grond
Type - PredefinedType: STANDARD; Material: Knauf Insulation_Ecose® glaswol_naturoll 032 200 mm
Type - Analytical Properties - Roughness: 1; Thermal mass: 0; Absorptance: 0.1; Heat Transfer Coefficient (U): 0.16; Thermal Resistance (R): 6.25
Type - Construction - Function: Exterior; Wrapping at Inserts: Do not wrap; Width: 200 mm
Type - Data - rollen / pak: 2; pak (m2): 2.32; pakken / pallet: 24; pallet (m2): 55.68
Type - Energy Analysis - kortstondige waterabsorptie: WS; langdurige waterabsorptie: WL(P); luchtstroomweerstand: Afr5; warmtegeleidingscoëfficiënt: 0.032; warmteweerstand: 6.25; waterdamptransmissie / waterdampdiffusie weerstandsfactor: MU1
Type - General - NLRS_C_content_creator: Cadix; NLRS_C_content_versie: V1.0
Type - Graphics - Coarse Scale Fill Color: 0
Type - Identity Data - Type Image: Raster image: Naturoll 032 .jpg (2); Assembly Code: 21; Assembly Description: Buitenwanden; Description: Naturoll 032 - 200mm; DoP nummer (Declaration of performance): G4220OPCPR; email: customerservice.nl@knaufinsulation.com; Manufacturer: Knauf Insulation B.V.; Model: Naturoll 032 is een onbeklede glaswoldeken met ECOSE® Technology; NLRS_C_Code_Brandklasse: A1; phone: +31(0)162-421245; product URL: https://www.knaufinsulation.nl/producten-van-knauf-insulation/naturoll-032; Type Name: NLRS_21_WA_Naturoll 032_200x580x2000mm; URL: www.knaufinsulation.nl
Type - Model Properties - diktebereik: 30 - 270; diktetolerantie: T4
Type - Other - Category: Walls; Family Name: Basic Wall
Type - Pset_ElementShading - Roughness: 304.8 mm
Type - Pset_ManufacturerTypeInformation - Manufacturer: Knauf Insulation B.V.
Type - Pset_ProductRequirements - Category: Walls
Type - Pset_QuantityTakeOff - Reference: NLRS_21_WA_Naturoll 032_200x580x2000mm
Type - Pset_ReinforcementBarPitchOfWall - Description: Naturoll 032 - 200mm; Reference: NLRS_21_WA_Naturoll 032_200x580x2000mm
Type - Pset_WallCommon - IsExternal: no; Reference: NLRS_21_WA_Naturoll 032_200x580x2000mm; ThermalTransmittance: 0.16 kg/K/s3
Classification: 21 Buitenwanden (Uniformat)
BaseQuantities - Height: 2000 mm; Width: 200 mm
Constraints - Related to Mass: no; Room Bounding: yes; Base Constraint: Level: Begane grond; Base Extension Distance: 0 mm; Base is Attached: no; Base Offset: 0 mm; Top Constraint: Level: Lengte; Top Extension Distance: 0 mm; Top is Attached: no; Top Offset: 0 mm; Unconnected Height: 2000 mm
Other - Family: Basic Wall: NLRS_21_WA_Naturoll 032_200x580x2000mm; Family and Type: Basic Wall: NLRS_21_WA_Naturoll 032_200x580x2000mm; Type: Basic Wall: NLRS_21_WA_Naturoll 032_200x580x2000mm; Type Id: Basic Wall: NLRS_21_WA_Naturoll 032_200x580x2000mm
Phasing - Phase Created: New Construction
Structural - Enable Analytical Model: no; Structural: no; Structural Usage: Non-bearing
Pset_WallCommon - LoadBearing: no; IsExternal: yes; ExtendToStructure: no
Name (Basic Wall:NLRS_21_WA_Naturoll 032_200x580x2000mm:...) | BaseQuantities, Length (mm) = Dimensions, Length (mm) | GrossFootprintArea (m2) | NetVolume (m3) | NetSideArea (m2) | Location Line | Area (m2) | Volume (m3)
26915 | 1000 | 0.2 | 400000000 | 2000000 | Core Face: Interior | 2 | 0.4
26917 | 1000 | 0.2 | 400000000 | 2000000 | Core Face: Interior | 2 | 0.4
26918 | 580 | 0.116 | 232000000 | 1160000 | Wall Centerline | 1.16 | 0.232

# IfcWallStandardCase: Basic Wall:NLRS_21_WA_Naturoll 032_245x580x2000mm (3)
In: Begane grond
Type - PredefinedType: STANDARD; Material: Knauf Insulation_Ecose® glaswol_naturoll 032 245 mm
Type - Analytical Properties - Roughness: 1; Thermal mass: 0; Absorptance: 0.1; Heat Transfer Coefficient (U): 0.130612; Thermal Resistance (R): 7.65625
Type - Construction - Function: Exterior; Wrapping at Inserts: Do not wrap; Width: 245 mm
Type - Data - rollen / pak: 2; pak (m2): 2.32; pakken / pallet: 18; pallet (m2): 41.76
Type - Energy Analysis - kortstondige waterabsorptie: WS; langdurige waterabsorptie: WL(P); luchtstroomweerstand: Afr5; warmtegeleidingscoëfficiënt: 0.032; warmteweerstand: 7.65; waterdamptransmissie / waterdampdiffusie weerstandsfactor: MU1
Type - General - NLRS_C_content_creator: Cadix; NLRS_C_content_versie: V1.0
Type - Graphics - Coarse Scale Fill Color: 0
Type - Identity Data - Type Image: Raster image: Naturoll 032 .jpg (2); Assembly Code: 21; Assembly Description: Buitenwanden; Description: Naturoll 032 - 245mm; DoP nummer (Declaration of performance): G4220OPCPR; email: customerservice.nl@knaufinsulation.com; Manufacturer: Knauf Insulation B.V.; Model: Naturoll 032 is een onbeklede glaswoldeken met ECOSE® Technology; NLRS_C_Code_Brandklasse: A1; phone: +31(0)162-421245; product URL: https://www.knaufinsulation.nl/producten-van-knauf-insulation/naturoll-032; Type Name: NLRS_21_WA_Naturoll 032_245x580x2000mm; URL: www.knaufinsulation.nl
Type - Model Properties - diktebereik: 30 - 270; diktetolerantie: T4
Type - Other - Category: Walls; Family Name: Basic Wall
Type - Pset_ElementShading - Roughness: 304.8 mm
Type - Pset_ManufacturerTypeInformation - Manufacturer: Knauf Insulation B.V.
Type - Pset_ProductRequirements - Category: Walls
Type - Pset_QuantityTakeOff - Reference: NLRS_21_WA_Naturoll 032_245x580x2000mm
Type - Pset_ReinforcementBarPitchOfWall - Description: Naturoll 032 - 245mm; Reference: NLRS_21_WA_Naturoll 032_245x580x2000mm
Type - Pset_WallCommon - IsExternal: no; Reference: NLRS_21_WA_Naturoll 032_245x580x2000mm; ThermalTransmittance: 0.130612 kg/K/s3
Classification: 21 Buitenwanden (Uniformat)
BaseQuantities - Height: 2000 mm; Width: 245 mm
Constraints - Related to Mass: no; Room Bounding: yes; Base Constraint: Level: Begane grond; Base Extension Distance: 0 mm; Base is Attached: no; Base Offset: 0 mm; Top Constraint: Level: Lengte; Top Extension Distance: 0 mm; Top is Attached: no; Top Offset: 0 mm; Unconnected Height: 2000 mm
Other - Family: Basic Wall: NLRS_21_WA_Naturoll 032_245x580x2000mm; Family and Type: Basic Wall: NLRS_21_WA_Naturoll 032_245x580x2000mm; Type: Basic Wall: NLRS_21_WA_Naturoll 032_245x580x2000mm; Type Id: Basic Wall: NLRS_21_WA_Naturoll 032_245x580x2000mm
Phasing - Phase Created: New Construction
Structural - Enable Analytical Model: no; Structural: no; Structural Usage: Non-bearing
Pset_WallCommon - LoadBearing: no; IsExternal: yes; ExtendToStructure: no
Name (Basic Wall:NLRS_21_WA_Naturoll 032_245x580x2000mm:...) | BaseQuantities, Length (mm) = Dimensions, Length (mm) | GrossFootprintArea (m2) | NetVolume (m3) | NetSideArea (m2) | Location Line | Area (m2) | Volume (m3)
26942 | 1000 | 0.245 | 490000000 | 2000000 | Core Face: Interior | 2 | 0.49
26944 | 1000 | 0.245 | 490000000 | 2000000 | Core Face: Interior | 2 | 0.49
26945 | 580 | 0.1421 | 284200000 | 1160000 | Wall Centerline | 1.16 | 0.2842

# IfcWallStandardCase: Basic Wall:NLRS_21_WA_Naturoll 032_90x580x3500mm (3)
In: Begane grond
Type - PredefinedType: STANDARD; Material: Knauf Insulation_Ecose® glaswol_naturoll 032 90 mm
Type - Analytical Properties - Roughness: 1; Thermal mass: 0; Absorptance: 0.1; Heat Transfer Coefficient (U): 0.355556; Thermal Resistance (R): 2.8125
Type - Construction - Function: Exterior; Width: 90 mm; Wrapping at Inserts: Do not wrap
Type - Data - rollen / pak: 2; pak (m2): 4.06; pakken / pallet: 24; pallet (m2): 97.44
Type - Energy Analysis - kortstondige waterabsorptie: WS; langdurige waterabsorptie: WL(P); luchtstroomweerstand: Afr5; warmtegeleidingscoëfficiënt: 0.032; warmteweerstand: 2.8; waterdamptransmissie / waterdampdiffusie weerstandsfactor: MU1
Type - General - NLRS_C_content_creator: Cadix; NLRS_C_content_versie: V1.0
Type - Graphics - Coarse Scale Fill Color: 0
Type - Identity Data - Type Image: Raster image: Naturoll 032 .jpg (2); Assembly Code: 21; Assembly Description: Buitenwanden; Description: Naturoll 032 - 90mm; DoP nummer (Declaration of performance): G4220OPCPR; email: customerservice.nl@knaufinsulation.com; Manufacturer: Knauf Insulation B.V.; Model: Naturoll 032 is een onbeklede glaswoldeken met ECOSE® Technology; NLRS_C_Code_Brandklasse: A1; phone: +31(0)162-421245; product URL: https://www.knaufinsulation.nl/producten-van-knauf-insulation/naturoll-032; Type Name: NLRS_21_WA_Naturoll 032_90x580x3500mm; URL: www.knaufinsulation.nl
Type - Model Properties - diktebereik: 30 - 270; diktetolerantie: T4
Type - Other - Category: Walls; Family Name: Basic Wall
Type - Pset_ElementShading - Roughness: 304.8 mm
Type - Pset_ManufacturerTypeInformation - Manufacturer: Knauf Insulation B.V.
Type - Pset_ProductRequirements - Category: Walls
Type - Pset_QuantityTakeOff - Reference: NLRS_21_WA_Naturoll 032_90x580x3500mm
Type - Pset_ReinforcementBarPitchOfWall - Description: Naturoll 032 - 90mm; Reference: NLRS_21_WA_Naturoll 032_90x580x3500mm
Type - Pset_WallCommon - IsExternal: no; Reference: NLRS_21_WA_Naturoll 032_90x580x3500mm; ThermalTransmittance: 0.355556 kg/K/s3
Classification: 21 Buitenwanden (Uniformat)
BaseQuantities - Height: 2000 mm; Width: 90 mm
Constraints - Related to Mass: no; Room Bounding: yes; Base Constraint: Level: Begane grond; Base Extension Distance: 0 mm; Base is Attached: no; Base Offset: 0 mm; Top Constraint: Level: Lengte; Top Extension Distance: 0 mm; Top is Attached: no; Top Offset: 0 mm; Unconnected Height: 2000 mm
Other - Family: Basic Wall: NLRS_21_WA_Naturoll 032_90x580x3500mm; Family and Type: Basic Wall: NLRS_21_WA_Naturoll 032_90x580x3500mm; Type: Basic Wall: NLRS_21_WA_Naturoll 032_90x580x3500mm; Type Id: Basic Wall: NLRS_21_WA_Naturoll 032_90x580x3500mm
Phasing - Phase Created: New Construction
Structural - Enable Analytical Model: no; Structural: no; Structural Usage: Non-bearing
Pset_WallCommon - LoadBearing: no; IsExternal: yes; ExtendToStructure: no
Name (Basic Wall:NLRS_21_WA_Naturoll 032_90x580x3500mm:...) | BaseQuantities, Length (mm) = Dimensions, Length (mm) | GrossFootprintArea (m2) | NetVolume (m3) | NetSideArea (m2) | Location Line | Area (m2) | Volume (m3)
25055 | 1000 | 0.09 | 180000000 | 2000000 | Core Face: Interior | 2 | 0.18
25177 | 1000 | 0.09 | 180000000 | 2000000 | Core Face: Interior | 2 | 0.18
25240 | 580 | 0.0522 | 104400000 | 1160000 | Wall Centerline | 1.16 | 0.1044
